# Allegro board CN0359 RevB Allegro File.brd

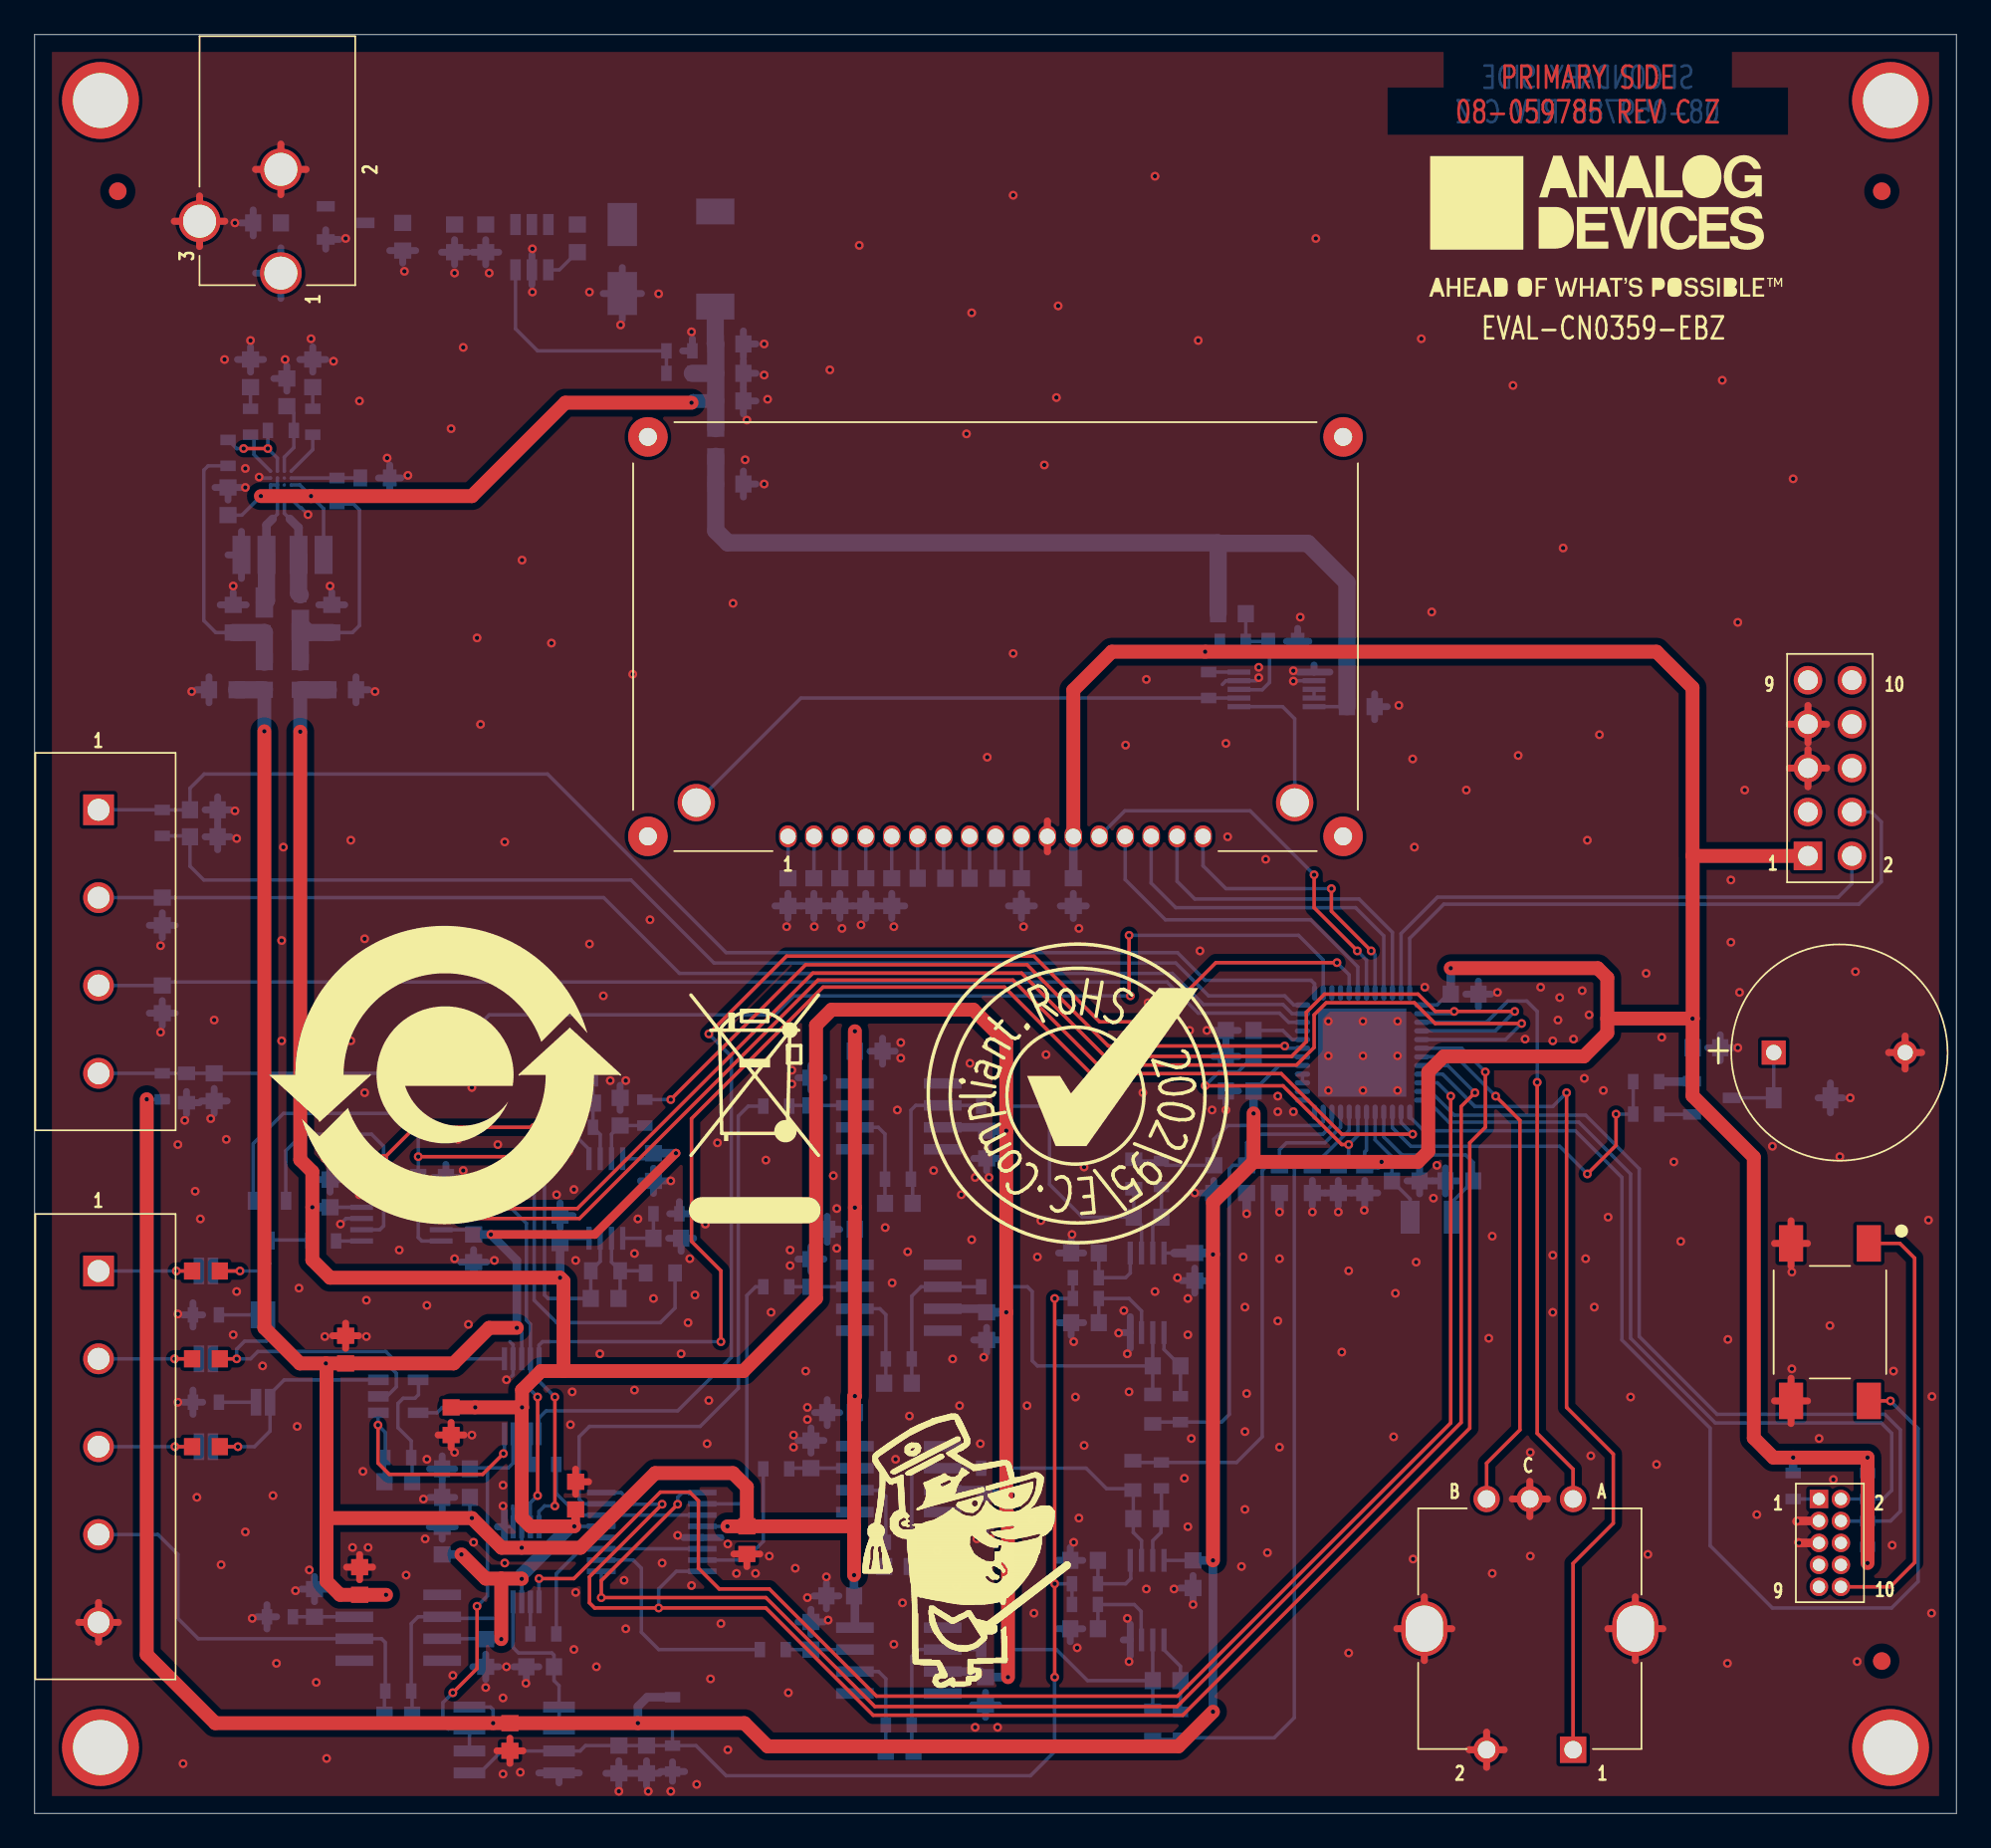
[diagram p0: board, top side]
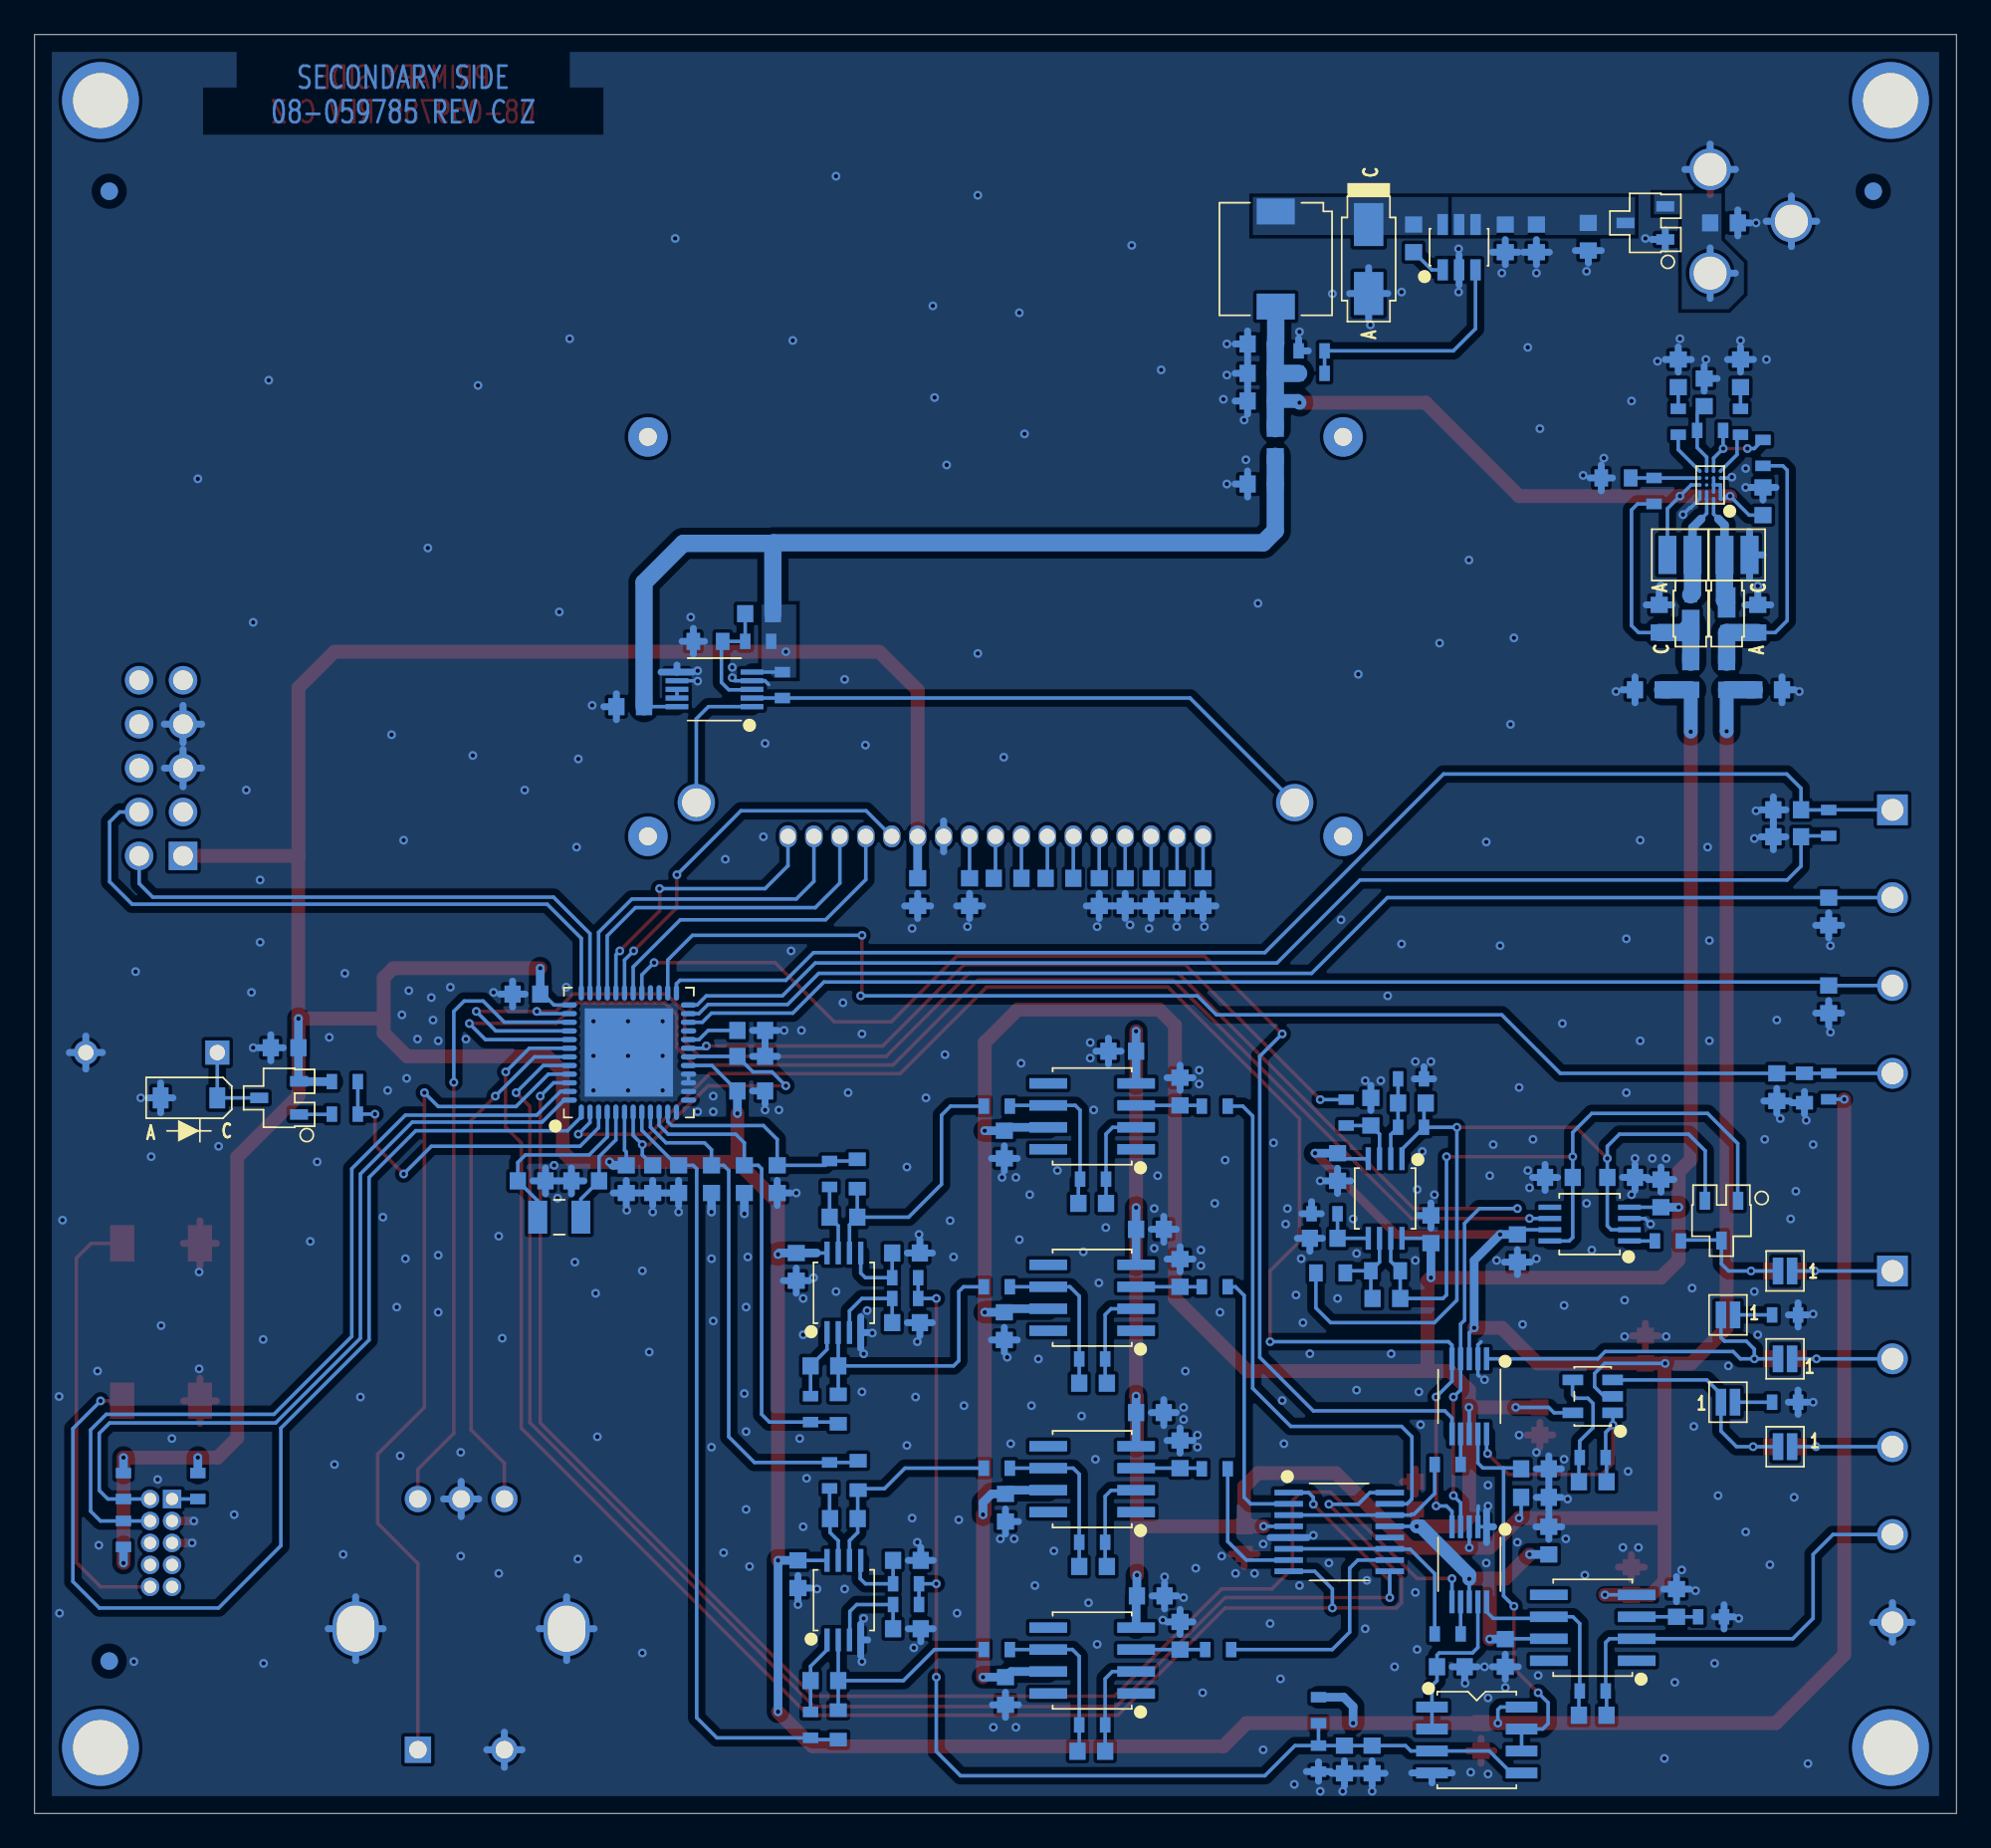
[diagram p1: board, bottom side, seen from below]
Outline 111.12 x 102.87 mm; copper layers: TOP, BOTTOM. Coordinates in mm from the lower left corner of the outline.
Outline path: 0,102.87 0,0 111.12,0 111.12,102.87 0,102.87

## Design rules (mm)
constraint set DEFAULT: min track width 0.203

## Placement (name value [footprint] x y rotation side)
C1  1UF  [C0603]  43.56 53.28 270 bottom
C2  1UF  [C0603]  17.98 26.82 90 top
C3  1UF  [C0603]  24.08 22.68 270 top
C4  1UF  [C0603]  31.29 18.38 90 top
C5  1UF  [C0603]  18.8 13.44 90 top
C6  1UF  [C0603]  41.19 15.8 270 top
C7  1UF  [C0603]  26.08 9.28 270 bottom
C8  1UF  [C0603]  27.48 4.42 270 top
C9  10uF  [C0603]  21.29 91.18 270 bottom
C12  10uF  [C0603]  11.19 75.88 90 bottom
C13  1UF  [C0603]  14.59 82.18 90 bottom
C15  0.1uF  [C0603]  13.44 91.98 180 bottom
C16  3300PF  [C0603]  12.49 83.28 90 bottom
C17  0.1uF  [C0603]  31.38 91.08 270 bottom
C18  10uF  [C0603]  24.29 91.08 270 bottom
C19  0.1uF  [C0603]  26.08 91.08 270 bottom
C21  10uF  [C0603]  17.18 69.09 90 bottom
C23  10uF  [C0603]  11.48 69.09 90 bottom
C24  1500PF  [C0603]  16.09 83.28 90 bottom
C25  0.1uF  [C0603]  40.19 84.98 0 bottom
C26  22UF  [C0603]  40.19 83.28 0 bottom
C27  0.1uF  [C0603]  76.69 64 0 bottom
C28  0.1uF  [C0603]  69.23 69.38 0 bottom
C29  0.01uF  [C0603]  17.79 64.98 0 bottom
C30  0.01uF  [C0603]  10.88 64.98 180 bottom
C31  10uF  [C0603]  40.19 81.68 0 bottom
C32  1UF  [C0603]  57.06 53.28 270 bottom
C33  1UF  [C0603]  54.86 54.08 0 bottom
C34  1UF  [C0603]  51.86 54.08 0 bottom
C35  0.1uF  [C0603]  60.06 53.28 270 bottom
C36  0.1uF  [C0603]  10.38 42 270 bottom
C37  0.1uF  [C0603]  7.38 52.16 270 bottom
C38  0.1uF  [C0603]  9.79 58.04 0 bottom
C39  0.1uF  [C0603]  9.79 56.48 0 bottom
C40  0.1uF  [C0603]  82.69 47.38 0 bottom
C41  0.1uF  [C0603]  7.38 47.08 270 bottom
C42  0.47UF  [C0603]  69.69 45.28 180 bottom
C43  0.1uF  [C0603]  96.67 44.28 0 bottom
C44  0.47UF  [C0603]  75.39 36.68 270 bottom
C45  1000pF  [C0603]  31.48 41.08 180 bottom
C46  1UF  [C0603]  35.79 37.38 270 bottom
C47  1UF  [C0603]  48.23 44.08 0 bottom
C48  1UF  [C0603]  69.69 41.78 180 bottom
C49  1UF  [C0603]  33.86 40.58 90 bottom
C50  4.7UF  [C0603]  44.89 41.75 90 bottom
C51  1UF  [C0603]  45.06 53.28 270 bottom
C52  0.01uF  [C0603]  68.19 36.68 270 bottom
C53  1UF  [C0603]  17.09 35.86 90 bottom
C54  1000pF  [C0603]  19.38 36.78 180 bottom
C55  820PF  [C0603]  64.36 34.48 0 bottom
C56  0.47UF  [C0603]  69.69 43.78 180 bottom
C57  0.1uF  [C0603]  76.91 36.68 270 bottom
C58  1UF  [C0603]  30.38 33.78 90 bottom
C59  1UF  [C0603]  36.59 33.26 0 bottom
C60  1000pF  [C0603]  49.97 35.28 0 bottom
C61  1UF  [C0603]  55.05 38.68 270 bottom
C62  1UF  [C0603]  60.74 32.41 180 bottom
C63  0.01uF  [C0603]  70.09 36.68 270 bottom
C64  0.01uF  [C0603]  73.89 36.68 270 bottom
C65  12pF  [C0603]  79.28 36.58 0 bottom
C66  12pF  [C0603]  82.39 36.58 180 bottom
C67  1000pF  [C0603]  22.98 36.78 0 bottom
C68  1000pF  [C0603]  32.96 29.78 180 bottom
C69  1UF  [C0603]  46.63 33.78 180 bottom
C70  1UF  [C0603]  25.38 32.68 270 bottom
C71  1UF  [C0603]  67.08 31.61 270 bottom
C72  0.01uF  [C0603]  71.98 36.68 270 bottom
C73  4.7UF  [C0603]  44.89 31.26 90 bottom
C74  1UF  [C0603]  60.74 28.38 180 bottom
C75  820PF  [C0603]  65.46 25.88 0 bottom
C76  1000pF  [C0603]  49.92 24.88 0 bottom
C77  1UF  [C0603]  55.05 28.18 270 bottom
C78  1000pF  [C0603]  21.03 19.18 180 bottom
C79  470pF  [C0603]  24.37 19.93 180 bottom
C80  1UF  [C0603]  46.63 23.18 180 bottom
C81  0.01uF  [C0603]  40.19 76.88 0 bottom
C82  1UF  [C0603]  24.37 18.28 180 bottom
C83  0.1uF  [C0603]  16.18 12.17 90 bottom
C84  4.7UF  [C0603]  44.89 20.77 90 bottom
C85  820PF  [C0603]  64.33 17.05 0 bottom
C86  1UF  [C0603]  23.57 15.78 90 bottom
C87  1000pF  [C0603]  49.92 14.28 0 bottom
C88  1UF  [C0603]  54.98 17.68 270 bottom
C89  1UF  [C0603]  60.69 14.63 180 bottom
C90  1UF  [C0603]  46.59 12.58 180 bottom
C91  1UF  [C0603]  66.98 13.83 270 bottom
C92  470pF  [C0603]  29.23 8.48 180 bottom
C93  4.7UF  [C0603]  44.89 10.28 90 bottom
C94  1UF  [C0603]  60.69 10.68 180 bottom
C95  1000pF  [C0603]  21.03 5.68 0 bottom
C96  820PF  [C0603]  65.46 7.68 0 bottom
C97  1000pF  [C0603]  50.02 3.6 0 bottom
C98  1UF  [C0603]  54.98 7.08 270 bottom
C99  1UF  [C0603]  33.79 3.12 270 bottom
C100  1UF  [C0603]  35.38 3.12 270 bottom
C101  1UF  [C0603]  46.56 53.28 270 bottom
C102  10uF  [C0603]  9.91 31.37 180 top
C103  1UF  [C0603]  9.91 26.29 0 top
C104  1UF  [C0603]  9.91 21.21 0 top
C105  1UF  [C0603]  48.06 53.28 270 bottom
C106  1UF  [C0603]  49.56 53.28 270 bottom
D1  PD3S140-7  [POWERDI323]  15.36 69.38 90 bottom
D2  PD3S140-7  [POWERDI323]  13.29 69.38 270 bottom
D3  B130-13-F  [SMA-2]  33.98 89.89 270 bottom
D4  MMSD4148T1G  [SOD123-2]  102.2 41.38 0 bottom
D5  BAT54SLT1G  [SOT23_B]  13.59 34.28 0 bottom
E1  100OHM  [L0603]  39.38 79.28 270 bottom
E2  100OHM  [L0603]  15.36 65.78 270 bottom
E3  100OHM  [L0603]  13.29 65.78 270 bottom
J1  PJ-102AH  [CNCUI-PJ-102A]  14.24 89.08 90 top
J2  SSW-105-01-G-D  [CNRCPT2X5H335LD35]  102.54 55.37 90 top
J3  OSTTC042162  [CNOSTTC042162]  3.7 58.04 270 top
J4  FTSH-105-01-L-D  [CNHDR2X5H219]  103.18 18.18 270 top
J5  OSTTC052162  [CNOSTTC052162]  3.7 31.37 270 top
JP1  -  [JPSLD02]  9.91 31.37 0 bottom
JP2  -  [JPSLD02]  9.91 26.29 0 bottom
JP3  -  [JPSLD02]  9.91 21.21 0 bottom
JP4  -  [JPSLD02]  13.21 28.83 0 bottom
JP5  -  [JPSLD02]  13.21 23.78 180 bottom
L1  4.7uH  [LSMSQ79H57]  15.99 72.78 0 bottom
L2  22UH  [LSMSQ236H189]  39.36 89.89 270 bottom
L3  8.2UH  [LSMSQ79H57]  12.69 72.78 0 bottom
NOREF  -  []  50.91 51.01 0 top
NOREF#2  -  []  86.46 3.98 0 top
NOREF#3  -  []  0 102.87 0 top
NOREF#4  -  [unnamed#2]  106.81 93.81 0 top
NOREF#5  -  []  140.51 149.31 0 top
NOREF#6  -  []  111.12 0 0 top
NOREF#7  -  []  0 0 0 top
NOREF#8  -  []  52.59 128.43 0 top
NOREF#9  -  []  0 102.87 270 top
NOREF#10  -  []  111.12 102.87 180 top
NOREF#11  -  []  126.31 186.91 0 top
NOREF#12  -  []  3.81 3.81 0 top
NOREF#13  -  [unnamed#2]  3.81 99.06 0 top
NOREF#14  -  []  23.71 42.71 0 top
NOREF#15  -  []  -22.69 -34.09 0 top
NOREF#16  -  []  111.12 0 90 top
NOREF#17  -  []  60.31 41.51 0 top
NOREF#18  -  []  3.81 3.81 0 top
NOREF#19  -  []  0 0 0 top
NOREF#20  -  [unnamed#2]  106.81 8.81 0 top
NOREF#21  -  []  -61.39 240.41 0 top
NOREF#22  -  []  0 102.87 0 top
NOREF#23  -  []  111.12 0 90 top
NOREF#24  -  []  0 0 0 top
NOREF#25  -  [unnamed#2]  107.31 99.06 0 top
NOREF#26  -  [unnamed#2]  107.31 3.81 0 top
NOREF#27  -  []  155.92 144.55 0 top
NOREF#28  -  []  -98.49 -107.79 0 top
NOREF#29  -  []  90.28 91.78 0 top
NOREF#30  -  [unnamed#2]  3.81 3.81 0 top
NOREF#31  -  [unnamed#2]  4.81 93.81 0 top
NOREF#32  -  []  85.48 94.48 270 top
NOREF#33  -  []  -106.09 -141.79 0 top
NOREF#34  -  []  121.61 28.31 0 top
NOREF#35  -  []  155.97 121.69 0 top
NOREF#36  -  [unnamed#2]  106.81 93.81 180 bottom
NOREF#37  -  [unnamed#2]  4.81 93.81 180 bottom
NOREF#38  -  [unnamed#2]  106.81 8.81 180 bottom
Q1  SMMBT3906LT3G  [SOT23_B]  96.98 41.38 90 bottom
R1  14.3K  [R0603]  16.09 80.48 90 bottom
R2  2.43K  [R0603]  37.29 84.58 0 bottom
R3  2.43MEG  [R0603]  17.48 76.48 90 bottom
R4  137K  [R0603]  19.68 77.23 0 bottom
R5  7.5K  [R0603]  37.29 83.28 180 bottom
R6  13.7  [R0603]  67.89 65.25 270 bottom
R7  35.7K  [R0603]  72.19 67.78 0 bottom
R8  5.11K  [R0603]  69.28 67.78 0 bottom
R9  0  [R0603]  101.69 18.93 270 bottom
R10  100K  [R0603]  105.98 16.16 90 bottom
R11  1K  [R0603]  7.38 42.05 90 bottom
R12  35.7  [R0603]  8.79 41.95 270 bottom
R13  1.5K  [R0603]  7.38 57.28 90 bottom
R14  110K  [R0603]  31.54 39.68 180 bottom
R15  15K  [R0603]  31.54 42.48 0 bottom
R16  13.3K  [R0603]  35.29 40.53 270 bottom
R17  47.5K  [R0603]  93.19 42.32 180 bottom
R18  2.74K  [R0603]  93.19 40.44 0 bottom
R19  7.5K  [R0603]  55.48 40.9 0 bottom
R20  1.2K  [R0603]  63.56 36.98 90 bottom
R21  24.3  [R0603]  65.16 36.98 90 bottom
R22  13.3K  [R0603]  36.53 34.68 180 bottom
R23  1K  [R0603]  16.68 33.1 0 bottom
R24  26.7K  [R0603]  36.19 31.26 180 bottom
R25  1K  [R0603]  49.92 36.68 0 bottom
R26  1K  [R0603]  60.79 30.98 0 bottom
R27  26.7K  [R0603]  33.01 31.38 180 bottom
R28  1K  [R0603]  60.79 29.78 0 bottom
R29  7.5K  [R0603]  55.48 30.46 0 bottom
R30  1K  [R0603]  49.97 26.28 0 bottom
R31  1.2K  [R0603]  64.66 23.38 270 bottom
R32  24.3  [R0603]  66.26 23.38 270 bottom
R33  432  [R0603]  29.42 20.18 0 bottom
R34  432  [R0603]  42.89 40.9 0 bottom
R35  475K  [R0603]  21.03 20.58 180 bottom
R36  432  [R0603]  42.89 30.46 0 bottom
R37  7.5K  [R0603]  55.48 19.97 0 bottom
R38  1.2K  [R0603]  63.51 19.55 90 bottom
R39  24.3  [R0603]  65.16 19.55 90 bottom
R40  1K  [R0603]  14.19 11.37 0 bottom
R41  432  [R0603]  42.89 19.93 0 bottom
R42  432  [R0603]  42.69 9.48 0 bottom
R43  1K  [R0603]  49.97 15.68 0 bottom
R44  1K  [R0603]  60.74 13.28 0 bottom
R45  432  [R0603]  29.42 10.38 0 bottom
R46  1K  [R0603]  60.74 12.08 0 bottom
R47  1K  [R0603]  21.03 7.08 0 bottom
R48  7.5K  [R0603]  55.48 9.48 0 bottom
R49  10K  [R0603]  36.89 5.97 270 bottom
R50  10K  [R0603]  36.89 3.17 270 bottom
R51  1K  [R0603]  49.97 5.12 0 bottom
R52  1.2K  [R0603]  64.66 5.12 270 bottom
R53  24.3  [R0603]  66.26 5.12 270 bottom
R54  100K  [R0603]  105.98 18.93 270 bottom
R55  1MEG  [R0603]  9.91 28.83 180 bottom
R56  1MEG  [R0603]  9.91 23.78 0 bottom
R57  2.32MEG  [R0603]  11.19 78.68 90 bottom
R58  118K  [R0603]  14.24 79.98 0 bottom
R59  10.5K  [R0603]  12.49 80.48 90 bottom
S1  PEC12R-4130F-S0012  [BOURNS_PEC12R-4XXXF-SXXXX]  88.96 3.68 180 top
S2  FSM2JSMA  [SWSMSQ236H185]  103.81 28.41 180 top
U1  NHD-C12832A1Z-NSW-BBW-3V3  [MNHD-C12832A1Z]  43.56 56.5 0 top
U2  WST-1203UX  [TORAD299D472H315]  100.56 44 0 top
U3  SI2343CDS-T1-GE3  [SOT23_B]  17.98 91.98 90 bottom
U4  ADP2300AUJZ  [TSOT23_6]  28.76 90.58 180 bottom
U5  ADP5072ACBZ  [WLCSP20H22]  14.24 76.82 90 bottom
U6  AD8592ARMZ  [RM10]  71.81 65 90 bottom
U7  ADUCM360BCPZ128  [QFN48_7X7_PAD5_1X5_1]  76.76 44 180 bottom
U9  ADA4077-2ARMZ  [MSOP8]  33.03 35.56 0 bottom
U10  ADA4638-1ARZ  [SO8]  49.97 40.31 90 bottom
U11  ADG1419BRMZ  [MSOP8]  21.21 34.08 90 bottom
U12  ADA4528-2ARMZ  [MSOP8]  64.33 30.11 180 bottom
U13  ADA4638-1ARZ  [SO8]  49.97 29.82 90 bottom
U14  ADA4622-1ARJZ  [SOT23-5L-2]  21.03 24.12 90 bottom
U15  AD8253ARMZ  [RM10]  28.17 24.12 0 bottom
U16  ADA4638-1ARZ  [SO8]  49.97 19.33 90 bottom
U17  ADG1211YRUZ  [TSSOP16]  35.69 16.28 270 bottom
U18  AD8253ARMZ  [RM10]  28.17 14.41 0 bottom
U19  ADA4627-1ARZ  [SO8]  21.03 10.74 90 bottom
U20  ADA4528-2ARMZ  [MSOP8]  64.33 12.33 180 bottom
U21  ADA4638-1ARZ  [SO8]  49.97 8.84 90 bottom
U22  AD8542ARZ  [SO8NB-5]  27.73 4.25 270 bottom
Y1  0.032768MEGHZ  [YSML126W59H35]  80.78 34.48 180 bottom

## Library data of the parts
C1-C8 C13 C32-C34 C46-C49 C51 C53 C58 C59 C61 C62 C69-C71 C74 C77 C80 C82 C86 C88-C91 C94 C98-C101 C103-C106 = CAP: User Part Number: UPN; Tolerance: 10; alternate symbols: (C0603L); part number: CAP_SM-1UF,25V,10,E048498,C0603; tolerance: 10
C9 C12 C18 C21 C23 C31 C102 = CAP: User Part Number: UPN; Tolerance: 10; alternate symbols: (C0603L); part number: CAP_SM-10UF,25V,10,E030977,C0603; tolerance: 10
C15 C17 C19 C25 C27 C28 C35-C41 C43 C57 C83 = CAP: User Part Number: UPN; Tolerance: 10; alternate symbols: (C0603L); part number: CAP_SM-0.1UF,25V,10,E038719,C0603; tolerance: 10
C16 = CAP: User Part Number: UPN; Tolerance: 10; alternate symbols: (C0603L); part number: CAP_SM-3300PF,25V,10,E058968,C0603; tolerance: 10
C24 = CAP: User Part Number: UPN; Tolerance: 10; alternate symbols: (C0603L); part number: CAP_SM-1500PF,16V,10,E058957,C0603; tolerance: 10
C26 = CAP: User Part Number: UPN; Tolerance: 20; alternate symbols: (C0603L); part number: CAP_SM-22UF,16V,20,E049658,C0603; tolerance: 20
C29 C30 C52 C63 C64 C72 C81 = CAP: User Part Number: UPN; Tolerance: 10; alternate symbols: (C0603L); part number: CAP_SM-0.01UF,50V,10,E018587,C0603; tolerance: 10
C42 C44 C56 = CAP: User Part Number: UPN; Tolerance: 10; alternate symbols: (C0603L); part number: CAP_SM-0.47UF,25V,10,E048456,C0603; tolerance: 10
C45 C54 C60 C67 C68 C76 C78 C87 C95 C97 = CAP: User Part Number: UPN; Tolerance: 10; alternate symbols: (C0603L); part number: CAP_SM-1000PF,50V,10,E018586,C0603; tolerance: 10
C50 C73 C84 C93 = CAP: User Part Number: UPN; Tolerance: 10; alternate symbols: (C0603L); part number: CAP_SM-4.7UF,25V,10,E058970,C0603; tolerance: 10
C55 C75 C85 C96 = CAP: User Part Number: UPN; Tolerance: 10; alternate symbols: (C0603L); part number: CAP_SM-820PF,50V,10,E058971,C0603; tolerance: 10
C65 C66 = CAP: User Part Number: UPN; Tolerance: 5; alternate symbols: (C0603L); part number: CAP_SM-12PF,50V,5,E000343,C0603; tolerance: 5
C79 C92 = CAP: User Part Number: UPN; Tolerance: 10; alternate symbols: (C0603L); part number: CAP_SM-470PF,50V,10,E025632,C0603; tolerance: 10
D1 D2 = DIOSCHOTTKY: Tolerance: N/A; User Part Number: UPN; alternate symbols: (); part number: DIOSCHOTTKY_SM-PD3S140-7,60V,N/A,E017965,POWERDI323; tolerance: N/A
D3 = DIOSCHOTTKY: User Part Number: UPN; Tolerance: N/A; alternate symbols: (); part number: DIOSCHOTTKY_SM-B130-13-F,30V,N/A,E029499,SMA-2; tolerance: N/A
D4 = DIO: User Part Number: UPN; Tolerance: N/A; alternate symbols: (); part number: DIO_SM-MMSD4148T1G,100V,N/A,E005349,SOD123-2; tolerance: N/A
D5 = DIOSCHOTTKY3P_V14: User Part Number: UPN; Tolerance: N/A; alternate symbols: (); part number: DIOSCHOTTKY3P_V14_SM-BAT54SLT1G,30V,N/A,E035143,SOT23_B; tolerance: N/A
E1-E3 = FERRITE: User Part Number: UPN; Tolerance: N/A; alternate symbols: (L0603L); part number: FERRITE_SM-100OHM,N/A,E011938,L0603; tolerance: N/A
J1 = CN3P: Tolerance: N/A; User Part Number: UPN; alternate symbols: (); part number: CN3P_TH-PJ-102AH,E010074,CNCUI-PJ-102A; tolerance: N/A
J2 = CN10P: Tolerance: N/A; User Part Number: UPN; alternate symbols: (); part number: CN10P_TH-SSW-105-01-G-D,E012830,CNRCPT2X5H335LD35; tolerance: N/A
J3 = CN4P: User Part Number: UPN; Tolerance: N/A; alternate symbols: (); part number: CN4P_TH-OSTTC042162,E027760,CNOSTTC042162; tolerance: N/A
J4 = CN10P_ODD_EVEN: Tolerance: N/A; User Part Number: UPN; alternate symbols: (); part number: CN10P_ODD_EVEN_TH-FTSH-105-01-L-D,E018623,CNHDR2X5H219; tolerance: N/A
J5 = CN5P: User Part Number: UPN; Tolerance: N/A; alternate symbols: (); part number: CN5P_TH-OSTTC052162,E025296,CNOSTTC052162; tolerance: N/A
JP1-JP5 = NC2P: User Part Number: UPN; Tolerance: N/A; alternate symbols: (); part number: NC2P_SM-JPSLD02,E006230,JPSLD02; tolerance: N/A
L1 = IND: Tolerance: 20; User Part Number: UPN; alternate symbols: (); part number: IND_SM-4.7UH,20,E016399,LSMSQ79H57; tolerance: 20
L2 = IND: Tolerance: 20; User Part Number: UPN; alternate symbols: (); part number: IND_SM-22UH,20,E040512,LSMSQ236H189; tolerance: 20
L3 = IND: Tolerance: 20; User Part Number: UPN; alternate symbols: (); part number: IND_SM-8.2UH,20,E047498,LSMSQ79H57; tolerance: 20
Q1 = TRANPNP_V3: User Part Number: UPN; Tolerance: N/A; alternate symbols: (); part number: TRANPNP_V3_SM-SMMBT3906LT3G,E056389,SOT23_B; tolerance: N/A
R1 = RES: User Part Number: UPN; Tolerance: 1; alternate symbols: (R0603L); part number: RES_SM-14.3K,E058987,1/10W,1,R0603; tolerance: 1
R2 = RES: User Part Number: UPN; Tolerance: 1; alternate symbols: (R0603L); part number: RES_SM-2.43K,E042601,1/10W,1,R0603; tolerance: 1
R3 = RES: User Part Number: UPN; Tolerance: 1; alternate symbols: (R0603L); part number: RES_SM-2.43MEG,E026607,1/10W,1,R0603; tolerance: 1
R4 = RES: User Part Number: UPN; Tolerance: 1; alternate symbols: (R0603L); part number: RES_SM-137K,E044643,1/10W,1,R0603; tolerance: 1
R5 = RES: User Part Number: UPN; Tolerance: 1; alternate symbols: (R0603L); part number: RES_SM-7.5K,E006439,1/10W,1,R0603; tolerance: 1
R6 = RES: User Part Number: UPN; Tolerance: 1; alternate symbols: (R0603L); part number: RES_SM-13.7,E058986,1/10W,1,R0603; tolerance: 1
R7 = RES: User Part Number: UPN; Tolerance: 1; alternate symbols: (R0603L); part number: RES_SM-35.7K,E016592,1/10W,1,R0603; tolerance: 1
R8 = RES: User Part Number: UPN; Tolerance: 1; alternate symbols: (R0603L); part number: RES_SM-5.11K,E026136,1/10W,1,R0603; tolerance: 1
R9 = RES: User Part Number: UPN; Tolerance: JUMPER; alternate symbols: (R0603L); part number: RES_SM-0,E054377,1/10W,JUMPER,R0603; tolerance: JUMPER
R10 R54 = RES: User Part Number: UPN; Tolerance: 1; alternate symbols: (R0603L); part number: RES_SM-100K,E017050,1/10W,1,R0603; tolerance: 1
R11 R23 R25 R26 R28 R30 R40 R43 R44 R46 R51 = RES: User Part Number: UPN; Tolerance: 1; alternate symbols: (R0603L); part number: RES_SM-1K,E029591,1/10W,1,R0603; tolerance: 1
R12 = RES: User Part Number: UPN; Tolerance: 1; alternate symbols: (R0603L); part number: RES_SM-35.7,E006398,1/10W,1,R0603; tolerance: 1
R13 = RES: User Part Number: UPN; Tolerance: 0.1; alternate symbols: (R0603L); part number: RES_SM-1.5K,E010316,1/10W,0.1,R0603; tolerance: 0.1
R14 = RES: User Part Number: UPN; Tolerance: 0.1; alternate symbols: (R0603L); part number: RES_SM-110K,E058984,1/10W,0.1,R0603; tolerance: 0.1
R15 = RES: User Part Number: UPN; Tolerance: 0.1; alternate symbols: (R0603L); part number: RES_SM-15K,E019547,1/10W,0.1,R0603; tolerance: 0.1
R16 R22 = RES: User Part Number: UPN; Tolerance: 1; alternate symbols: (R0603L); part number: RES_SM-13.3K,E049888,1/10W,1,R0603; tolerance: 1
R17 = RES: User Part Number: UPN; Tolerance: 1; alternate symbols: (R0603L); part number: RES_SM-47.5K,E032237,1/10W,1,R0603; tolerance: 1
R18 = RES: User Part Number: UPN; Tolerance: 1; alternate symbols: (R0603L); part number: RES_SM-2.74K,E003698,1/10W,1,R0603; tolerance: 1
R19 R29 R37 R48 = RES: User Part Number: UPN; Tolerance: 0.1; alternate symbols: (R0603L); part number: RES_SM-7.5K,E059024,1/5W,0.1,R0603; tolerance: 0.1
R20 R31 R38 R52 = RES: User Part Number: UPN; Tolerance: 0.1; alternate symbols: (R0603L); part number: RES_SM-1.2K,E039264,1/10W,0.1,R0603; tolerance: 0.1
R21 R32 R39 R53 = RES: User Part Number: UPN; Tolerance: 1; alternate symbols: (R0603L); part number: RES_SM-24.3,E059028,1/10W,1,R0603; tolerance: 1
R24 R27 = RES: User Part Number: UPN; Tolerance: 0.1; alternate symbols: (); part number: RES_SM-26.7K,E059128,1/5W,0.1,R0603; tolerance: 0.1
R33 R34 R36 R41 R42 R45 = RES: User Part Number: UPN; Tolerance: 1; alternate symbols: (R0603L); part number: RES_SM-432,E059030,1/10W,1,R0603; tolerance: 1
R35 = RES: User Part Number: UPN; Tolerance: 1; alternate symbols: (R0603L); part number: RES_SM-475K,E032846,1/10W,1,R0603; tolerance: 1
R47 = RES: User Part Number: UPN; Tolerance: 0.1; alternate symbols: (R0603L); part number: RES_SM-1K,E010662,1/10W,0.1,R0603; tolerance: 0.1
R49 R50 = RES: User Part Number: UPN; Tolerance: 1; alternate symbols: (R0603L); part number: RES_SM-10K,E058983,1/10W,1,R0603; tolerance: 1
R55 R56 = RES: User Part Number: UPN; Tolerance: 1; alternate symbols: (R0603L); part number: RES_SM-1MEG,E003682,1/10W,1,R0603; tolerance: 1
R57 = RES: User Part Number: UPN; Tolerance: 1; alternate symbols: (R0603L); part number: RES_SM-2.32MEG,E029679,1/10W,1,R0603; tolerance: 1
R58 = RES: User Part Number: UPN; Tolerance: 1; alternate symbols: (R0603L); part number: RES_SM-118K,E058985,1/10W,1,R0603; tolerance: 1
R59 = RES: User Part Number: UPN; Tolerance: 1; alternate symbols: (R0603L); part number: RES_SM-10.5K,E058980,1/10W,1,R0603; tolerance: 1
S1 = SWENCODER5P_2PSHLD: User Part Number: UPN; Tolerance: N/A; alternate symbols: (); part number: SWENCODER5P_2PSHLD_TH-PEC12R-4130F-S0012,E027763,BOURNS_PEC12R-4XXXF-SXXXX; tolerance: N/A
S2 = SWSPST4PIN_B: User Part Number: UPN; Tolerance: N/A; alternate symbols: (); part number: SWSPST4PIN_B_SM-FSM2JSMA,E016530,SWSMSQ236H185; tolerance: N/A
U1 = MOD_NHD_C12832A1Z: User Part Number: UPN; Tolerance: N/A; alternate symbols: (); part number: MOD_NHD_C12832A1Z_TH-NHD-C12832A1Z-NSW-BBW-3V3,E019272,MNHD-C12832A1Z; tolerance: N/A
U2 = ICWST_1203UX: User Part Number: UPN; Tolerance: N/A; alternate symbols: (); part number: ICWST_1203UX_TH-WST-1203UX,E050821,TORAD299D472H315; tolerance: N/A
U3 = TRANPMOSFET_V12: User Part Number: UPN; Tolerance: N/A; alternate symbols: (); part number: TRANPMOSFET_V12_SM-SI2343CDS-T1-GE3,E042394,SOT23_B; tolerance: N/A
U4 = ADP2301: User Part Number: UPN; Tolerance: N/A; alternate symbols: (); part number: ADP2301_SM-ADP2300AUJZ,E013639,TSOT23_6; tolerance: N/A
U5 = ADP5072: Tolerance: N/A; User Part Number: UPN; alternate symbols: (); part number: ADP5072_SM-ADP5072ACBZ,E030798,WLCSP20H22; tolerance: N/A
U6 = AD8592: Tolerance: N/A; User Part Number: UPN; alternate symbols: (); part number: AD8592_SM-AD8592ARMZ,E025174,RM10; tolerance: N/A
U7 = ADUCM36X: User Part Number: UPN; Tolerance: N/A; alternate symbols: (); part number: ADUCM36X_SM-ADUCM360BCPZ128,E018148,QFN48_7X7_PAD5_1X5_1; tolerance: N/A
U9 = ADA4077_2: Tolerance: N/A; User Part Number: UPN; alternate symbols: (); part number: ADA4077_2_SM-ADA4077-2ARMZ,E026580,MSOP8; tolerance: N/A
U10 U13 U16 U21 = ADOPAMP1V4: Tolerance: N/A; User Part Number: UPN; alternate symbols: (); part number: ADOPAMP1V4_SM-ADA4638-1ARZ,E015446,SO8; tolerance: N/A
U11 = ADG1419: Tolerance: N/A; User Part Number: UPN; alternate symbols: (); part number: ADG1419_SM-ADG1419BRMZ,E014853,MSOP8; tolerance: N/A
U12 U20 = ADA4528_2: Tolerance: N/A; User Part Number: UPN; alternate symbols: (); part number: ADA4528_2_SM-ADA4528-2ARMZ,E018592,MSOP8; tolerance: N/A
U14 = ADA4622_1_V2: User Part Number: UPN; Tolerance: N/A; alternate symbols: (); part number: ADA4622_1_V2_SM-ADA4622-1ARJZ,E038112,SOT23-5L-2; tolerance: N/A
U15 U18 = AD8253: Tolerance: N/A; User Part Number: UPN; alternate symbols: (); part number: AD8253_SM-AD8253ARMZ,E008097,RM10; tolerance: N/A
U17 = ADG1611: Tolerance: N/A; User Part Number: UPN; alternate symbols: (); part number: ADG1611_SM-ADG1211YRUZ,E012179,TSSOP16; tolerance: N/A
U19 = ADA46X7: Tolerance: N/A; User Part Number: UPN; alternate symbols: (); part number: ADA46X7_SM-ADA4627-1ARZ,E012263,SO8; tolerance: N/A
U22 = ADOPAMP2: Tolerance: N/A; User Part Number: UPN; alternate symbols: (); part number: ADOPAMP2_SM-AD8542ARZ,E004993,SO8NB-5; tolerance: N/A
Y1 = XTAL: User Part Number: UPN; Tolerance: 20PPM; alternate symbols: (); part number: XTAL_SM-0.032768MEGHZ,E019185,YSML126W59H35; tolerance: 20PPM

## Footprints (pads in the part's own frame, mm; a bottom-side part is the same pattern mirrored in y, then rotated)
BOURNS_PEC12R-4XXXF-SXXXX
  rect 1.524x1.524 hole 1.016: 1(0,0)
  round 1.524 hole 1.016: 2(5,0) A(0,-14.5) B(5,-14.5) C(2.5,-14.5)
  oval 2.667x3.175 hole 2.159x2.667: SH1(-3.6,-7) SH2(8.6,-7)
C0603
  rect 0.94x0.991 smd: 1(-0.8,0) 2(0.8,0)
CNCUI-PJ-102A
  round 2.413 hole 1.905: 1(0,0) 2(6,0) 3(3,4.7)
CNHDR2X5H219
  rect 1.067x1.067 hole 0.711: 1(0,0)
  round 1.067 hole 0.711: 2(0,1.27) 3(1.27,0) 4(1.27,1.27) 5(2.54,0) 6(2.54,1.27) 7(3.81,0) 8(3.81,1.27) 9(5.08,0) 10(5.08,1.27)
CNOSTTC042162
  rect 1.778x1.778 hole 1.27: 1(0,0)
  round 1.778 hole 1.27: 2(5.08,0) 3(10.16,0) 4(15.24,0)
CNOSTTC052162
  rect 1.778x1.778 hole 1.27: 1(0,0)
  round 1.778 hole 1.27: 2(5.08,0) 3(10.16,0) 4(15.24,0) 5(20.32,0)
CNRCPT2X5H335LD35
  rect 1.651x1.651 hole 1.143: 1(0,0)
  round 1.651 hole 1.143: 2(0,-2.54) 3(2.54,0) 4(2.54,-2.54) 5(5.08,0) 6(5.08,-2.54) 7(7.62,0) 8(7.62,-2.54) 9(10.16,0) 10(10.16,-2.54)
JPSLD02
  rect 0.61x1.549 smd: 1(-0.406,0) 2(0.406,0)
L0603
  rect 0.94x0.991 smd: 1(-0.8,0) 2(0.8,0)
LSMSQ79H57
  rect 1.041x2.21 smd: 1(-0.724,0) 2(0.724,0)
LSMSQ236H189
  rect 1.499x2.21 smd: 1(-2.749,0) 2(2.749,0)
MNHD-C12832A1Z
  round 2.286 hole 1.041 unplated: (-8.1,23.1) (-8.1,0) (32.1,23.1) (32.1,0)
  oval 1.016x1.27 hole 0.889: 1(0,0) 2(1.5,0) 3(3,0) 4(4.5,0) 5(6,0) 6(7.5,0) 7(9,0) 8(10.5,0) 9(12,0) 10(13.5,0) 11(15,0) 12(16.5,0) 13(18,0) 14(19.5,0) 15(21,0) 16(22.5,0) 17(24,0)
  round 2.159 hole 1.651: A(-5.3,1.95) K(29.3,1.95)
MSOP8
  rect 0.305x1.321 smd: 1(-0.975,-2.3) 2(-0.325,-2.3) 3(0.325,-2.3) 4(0.975,-2.3) 5(0.975,2.3) 6(0.325,2.3) 7(-0.325,2.3) 8(-0.975,2.3)
POWERDI323
  rect 0.864x0.737 smd: A(1.09,0)
  rect 1.753x1.016 smd: C(-0.65,0)
QFN48_7X7_PAD5_1X5_1
  oval 0.305x0.889 smd: 1(-2.75,-3.45) 2(-2.25,-3.45) 3(-1.75,-3.45) 4(-1.25,-3.45) 5(-0.75,-3.45) 6(-0.25,-3.45) 7(0.25,-3.45) 8(0.75,-3.45) 9(1.25,-3.45) 10(1.75,-3.45) 11(2.25,-3.45) 12(2.75,-3.45) 25(2.75,3.45) 26(2.25,3.45) 27(1.75,3.45) 28(1.25,3.45) 29(0.75,3.45) 30(0.25,3.45) 31(-0.25,3.45) 32(-0.75,3.45) 33(-1.25,3.45) 34(-1.75,3.45) 35(-2.25,3.45) 36(-2.75,3.45)
  oval 0.889x0.305 smd: 13(3.45,-2.75) 14(3.45,-2.25) 15(3.45,-1.75) 16(3.45,-1.25) 17(3.45,-0.75) 18(3.45,-0.25) 19(3.45,0.25) 20(3.45,0.75) 21(3.45,1.25) 22(3.45,1.75) 23(3.45,2.25) 24(3.45,2.75) 37(-3.45,2.75) 38(-3.45,2.25) 39(-3.45,1.75) 40(-3.45,1.25) 41(-3.45,0.75) 42(-3.45,0.25) 43(-3.45,-0.25) 44(-3.45,-0.75) 45(-3.45,-1.25) 46(-3.45,-1.75) 47(-3.45,-2.25) 48(-3.45,-2.75)
  rect 5.105x5.105 smd: PAD(0,0)
R0603
  rect 0.61x0.889 smd: 1(-0.75,0) 2(0.75,0)
RM10
  rect 0.305x1.321 smd: 1(-1,-2.171) 2(-0.5,-2.171) 3(0,-2.171) 4(0.5,-2.171) 5(1,-2.171) 6(1,2.171) 7(0.5,2.171) 8(0,2.171) 9(-0.5,2.171) 10(-1,2.171)
SMA-2
  rect 2.489x1.702 smd: A(1.995,0) C(-1.995,0)
SO8
  rect 0.61x2.184 smd: 1(-1.905,-2.54) 2(-0.635,-2.54) 3(0.635,-2.54) 4(1.905,-2.54) 5(1.905,2.54) 6(0.635,2.54) 7(-0.635,2.54) 8(-1.905,2.54)
SO8NB-5
  rect 0.635x1.829 smd: 1(-1.905,-2.591) 2(-0.635,-2.591) 3(0.635,-2.591) 4(1.905,-2.591) 5(1.905,2.591) 6(0.635,2.591) 7(-0.635,2.591) 8(-1.905,2.591)
SOD123-2
  rect 0.914x1.219 smd: A(1.638,0) C(-1.638,0)
SOT23-5L-2
  rect 0.61x1.194 smd: 1(-0.95,-1.15) 2(0,-1.15) 3(0.95,-1.15) 4(0.95,1.15) 5(-0.95,1.15)
SOT23_B
  rect 0.61x1.041 smd: 1(-0.958,-1.15) 2(0.958,-1.15) 3(0,1.15)
SWSMSQ236H185
  rect 1.397x2.108 smd: 1(-2.248,-4.554) 2(-2.248,4.554) 3(2.248,-4.554) 4(2.248,4.554)
TORAD299D472H315
  round 1.397 hole 0.889: N(7.6,0)
  rect 1.397x1.397 hole 0.889: P(0,0)
TSOT23_6
  rect 0.61x1.219 smd: 1(-0.95,-1.31) 2(0,-1.31) 3(0.95,-1.31) 4(0.95,1.31) 5(0,1.31) 6(-0.95,1.31)
TSSOP16
  rect 0.33x1.651 smd: 1(-2.275,-2.92) 2(-1.625,-2.92) 3(-0.975,-2.92) 4(-0.325,-2.92) 5(0.325,-2.92) 6(0.975,-2.92) 7(1.625,-2.92) 8(2.275,-2.92) 9(2.275,2.92) 10(1.625,2.92) 11(0.975,2.92) 12(0.325,2.92) 13(-0.325,2.92) 14(-0.975,2.92) 15(-1.625,2.92) 16(-2.275,2.92)
unnamed#2
  round 1.016 smd: (0,0)
WLCSP20H22
  round 0.203 smd: A1(-0.8,-0.6) A2(-0.8,-0.2) A3(-0.8,0.2) A4(-0.8,0.6) B1(-0.4,-0.6) B2(-0.4,-0.2) B3(-0.4,0.2) B4(-0.4,0.6) C1(0,-0.6) C2(0,-0.2) C3(0,0.2) C4(0,0.6) D1(0.4,-0.6) D2(0.4,-0.2) D3(0.4,0.2) D4(0.4,0.6) E1(0.8,-0.6) E2(0.8,-0.2) E3(0.8,0.2) E4(0.8,0.6)
YSML126W59H35
  rect 1.092x1.905 smd: 1(-1.246,0) 2(1.246,0)

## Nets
+3.3V: C8.1 C27.1 C28.1 C35.1 C40.1 C43.1 C48.1 C57.1 C71.1 C81.1 C91.1 E1.2(N2) J2.1 Q1.2(E) R6.1 R8.1 R9.1 R10.1 R11.1 R17.1 R49.1 R54.1 U1.12 U6.5 U6.10 U7.6 U7.17 U7.37 U12.8 U20.8 U22.8
+15V: C3.1 C4.1 C7.1 C29.1 C53.1 C58.1 C61.1 C77.1 C86.1 C88.1 C98.1 E2.2(N2) U9.8 U10.7 U11.4 U13.7 U14.5 U15.8 U16.7 U17.13 U18.8 U19.7 U21.7
-15V: C2.1 C5.1 C6.1 C30.1 C46.1 C47.1 C69.1 C70.1 C80.1 C82.1 C90.1 E3.2(N2) U9.4(V-) U10.4(V-) U11.7(VSS) U13.4(V-) U14.2(V-) U15.3 U16.4(V-) U17.4(VSS) U18.3 U19.4(V-) U21.4(V-)
GND: C1.2(N2) C2.2(N2) C3.2(N2) C4.2(N2) C5.2(N2) C6.2(N2) C7.2(N2) C8.2(N2) C9.2(N2) C12.2(N2) C13.2(N2) C15.2(N2) C16.2(N2) C18.2(N2) C19.2(N2) C21.2(N2) C23.2(N2) C24.2(N2) C25.2(N2) C26.2(N2) C27.2(N2) C29.2(N2) C30.2(N2) C31.2(N2) C32.2(N2) C35.2(N2) C36.2(N2) C37.2(N2) C38.2(N2) C39.2(N2) C40.2(N2) C41.2(N2) C42.2(N2) C43.2(N2) C44.2(N2) C46.2(N2) C47.2(N2) C48.2(N2) C49.2(N2) C50.2(N2) C51.2(N2) C52.2(N2) C53.2(N2) C54.2(N2) C56.2(N2) C57.2(N2) C58.2(N2) C59.2(N2) C61.2(N2) C62.2(N2) C63.2(N2) C64.2(N2) C65.2(N2) C66.2(N2) C67.2(N2) C69.2(N2) C70.2(N2) C71.2(N2) C72.2(N2) C73.2(N2) C74.2(N2) C77.2(N2) C79.2(N2) C80.2(N2) C81.2(N2) C82.2(N2) C83.2(N2) C84.2(N2) C86.2(N2) C88.2(N2) C89.2(N2) C90.2(N2) C91.2(N2) C92.2(N2) C93.2(N2) C94.2(N2) C98.2(N2) C99.2(N2) C100.2(N2) C101.2(N2) C105.2(N2) C106.2(N2) D3.A(P) D4.A(P) J1.2 J1.3(N3) J2.5 J2.7 J4.3 J4.5 J5.5(N5) L3.1 R2.2(N2) R4.2(N2) R7.2(N2) R12.2(N2) R15.1 R22.1 R40.1 R50.2(N2) R55.2(N2) R56.1 S1.2 S1.C S1.SH1 S1.SH2 S2.3 S2.4(N4) U1.11(VSS) U2.N(N2) U3.1 U4.2 U5.A4 U5.B4 U5.D1 U6.4(V-) U6.6 U6.7 U7.14 U7.15 U7.16 U7.PAD U11.3 U12.4(V-) U15.2 U17.5 U18.1 U18.2 U20.4(V-) U22.4(V-)
V1A: R34.1 U17.15
V1B: R36.1 U17.2
V2A: R41.1 U17.7
V2B: R42.1 U17.10
VCC: C9.1 C18.1 C19.1 U3.3 U4.4 U4.5(VIN)
+VEXC: C45.2(N2) C54.1 D5.2 R14.2(N2) R24.1 U9.1 U11.2
-VEXC: C67.1 C68.2(N2) D5.1 R27.2(N2) U9.7 U11.8
AD8253_A0: U7.38 U7.40 U15.4 U18.4
AD8253_A1: U7.2 U15.5 U18.5
AD8253_WR0: U7.29 U15.6(WR_N)
AD8253_WR1: U7.46 U18.6(WR_N)
ADC0: C64.1 R52.2(N2) R53.2(N2) U7.8
ADC1: C72.1 R38.2(N2) R39.2(N2) U7.9
ADC2: C63.1 R31.2(N2) R32.2(N2) U7.10
ADC3: C52.1 R20.2(N2) R21.2(N2) U7.11
DAC: R16.1 U7.19
FB1: C21.1 D1.C E2.1 R3.1
FB2: C23.1 D2.A(P) E3.1 R57.1
LCD_A0: U1.15 U7.33
LCD_BACKLIGHT_LED+: R6.2(N2) U1.A U6.2
LCD_BACKLIGHT_LED-: U1.K U6.1
LCD_CSB: U1.17 U7.32
LCD_MOSI: U1.13 U7.31
LCD_RST: U1.16 U7.34
LCD_SCLK: U1.14 U7.30
PWM0: U7.41 U11.6
PWM1: U7.42 U17.8 U17.16
PWM2: U7.44 U17.1 U17.9
SWCLK: J4.4 R10.2(N2) U7.47
SWDIO: J4.2 R54.2(N2) U7.48
UNNAMED_2_AD8592_I160_: U6.8 U6.9
UNNAMED_2_AD8592_I160__1: C28.2(N2) R7.1 R8.2(N2) U6.3
UNNAMED_2_ADUCM36X_I1_AIN5: C41.1 J3.3 U7.22
UNNAMED_2_ADUCM36X_I1_AIN6: C37.1 J3.2 U7.23
UNNAMED_2_ADUCM36X_I1_AIN7: C39.1 R13.1 U7.24
UNNAMED_2_ADUCM36X_I1_AIN9: C36.1 J3.4(N4) R11.2(N2) R12.1 U7.26
UNNAMED_2_ADUCM36X_I1_AVDDREG: C44.1 C56.1 U7.7 U7.18
UNNAMED_2_ADUCM36X_I1_INTREF: C42.1 U7.20
UNNAMED_2_ADUCM36X_I1_P0: J2.2 U7.35
UNNAMED_2_ADUCM36X_I1_P0_1: J2.4 U7.36
UNNAMED_2_ADUCM36X_I1_P1: S1.A U7.39
UNNAMED_2_ADUCM36X_I1_P1_1: S1.B U7.43
UNNAMED_2_ADUCM36X_I1_P1_2: S1.1 U7.45
UNNAMED_2_ADUCM36X_I1_P2: R17.2(N2) R18.1 U7.3
UNNAMED_2_ADUCM36X_I1_RESETN: S2.2 U7.1
UNNAMED_2_CAP_I152_N1: C34.1 U1.6
UNNAMED_2_CAP_I152_N2: C34.2(N2) U1.7
UNNAMED_2_CAP_I153_N1: C33.1 U1.8
UNNAMED_2_CAP_I153_N2: C33.2(N2) U1.9
UNNAMED_2_CAP_I154_N1: C32.1 U1.10
UNNAMED_2_CAP_I156_N1: C1.1 U1.1
UNNAMED_2_CAP_I171_N1: C51.1 U1.2
UNNAMED_2_CAP_I172_N1: C101.1 U1.3
UNNAMED_2_CAP_I173_N1: C105.1 U1.4
UNNAMED_2_CAP_I174_N1: C106.1 U1.5
UNNAMED_2_CN4P_I8_N1: C38.1 J3.1 R13.2(N2) U7.25
UNNAMED_2_CN10PODDEVEN_I92_N5: J4.10(N5) S2.1
UNNAMED_2_CN10PODDEVEN_I95_N1: J4.1 R9.2(N2)
UNNAMED_2_DIO_I30_N: D4.C Q1.3 U2.P
UNNAMED_2_RES_I133_N2: Q1.1 R18.2(N2)
UNNAMED_3_ADA40772_I167_: C45.1 R14.1 R15.2(N2) U9.2
UNNAMED_3_ADA40772_I167__1: C49.1 R16.2(N2) U9.3
UNNAMED_3_ADA40772_I180_: C68.1 R24.2(N2) R27.1 U9.6
UNNAMED_3_ADA40772_I180__1: C59.1 R22.2(N2) U9.5
UNNAMED_3_ADP2301_I1_BST: C17.2(N2) U4.1
UNNAMED_3_ADP2301_I1_FB: R2.1 R5.2(N2) U4.3
UNNAMED_3_ADP2301_I1_SW: C17.1 D3.C L2.1 U4.6
UNNAMED_3_ADP5072_I216_AVIN: C12.1 C25.1 C26.1 C31.1 E1.1 L1.2(N2) L2.2(N2) R5.1 U5.A1 U5.B1 U5.B2 U5.C1 U5.C2 U5.C4 U5.D2
UNNAMED_3_ADP5072_I216_COMP1: R1.1 U5.E4
UNNAMED_3_ADP5072_I216_COMP2: R59.1 U5.E1
UNNAMED_3_ADP5072_I216_FB1: R3.2(N2) R4.1 U5.D4
UNNAMED_3_ADP5072_I216_FB2: R57.2(N2) R58.1 U5.E2
UNNAMED_3_ADP5072_I216_SW2: D2.C L3.2(N2) U5.A2
UNNAMED_3_ADP5072_I216_SW11: D1.A(P) L1.1 U5.A3 U5.B3
UNNAMED_3_ADP5072_I216_VREF: C13.1 R58.2(N2) U5.E3(VREF)
UNNAMED_3_CAP_I106_N1: C15.1 J1.1 U3.2(S)
UNNAMED_3_CAP_I220_N1: C24.1 R1.2(N2)
UNNAMED_3_CAP_I221_N1: C16.1 R59.2(N2)
UNNAMED_4_AD8253_I20_OUT: R45.1 U18.7
UNNAMED_4_AD8253_I20_REF: C92.1 U18.9 U22.1 U22.2
UNNAMED_4_AD8253_I171_INNEG: C103.2(N2) JP2.2(N2) JP4.2(N2) U15.1
UNNAMED_4_AD8253_I171_INPOS: C78.2(N2) R35.2(N2) U14.1 U15.10
UNNAMED_4_AD8253_I171_OUT: R33.1 U15.7
UNNAMED_4_AD8253_I171_REF: C79.1 U15.9 U22.6 U22.7
UNNAMED_4_ADA46X7_I119_: C95.1 J5.4 R47.1 U19.2
UNNAMED_4_ADA46X7_I119__1: C83.1 R40.2(N2) U19.3
UNNAMED_4_ADA46X7_I119_OUT: C95.2(N2) R47.2(N2) U18.10 U19.6
UNNAMED_4_ADA46221V2_I6_: C78.1 R35.1 U14.4
UNNAMED_4_ADG1419_I1_D: R23.2(N2) U11.1
UNNAMED_4_ADG1611_I193_S1: R33.2(N2) U17.3 U17.14
UNNAMED_4_ADG1611_I193_S3: R45.2(N2) U17.6 U17.11
UNNAMED_4_CAP_I166_N1: C103.1 J5.2 JP2.1
UNNAMED_4_CAP_I167_N1: C104.1 J5.3 JP3.1
UNNAMED_4_CAP_I167_N2: C104.2(N2) JP3.2(N2) JP5.1 U14.3
UNNAMED_4_CAP_I168_N1: C102.1 D5.3(N3) JP1.2(N2) R23.1
UNNAMED_4_CAP_I168_N2: C102.2(N2) J5.1 JP1.1
UNNAMED_4_NC2P_I230_N1: JP4.1 R55.1
UNNAMED_4_NC2P_I231_N2: JP5.2(N2) R56.2(N2)
UNNAMED_5_ADA45282_I8_: C75.1 R29.2(N2) R31.1 U12.2
UNNAMED_5_ADA45282_I8__1: C74.1 R28.2(N2) U12.3
UNNAMED_5_ADA45282_I8_OUT: C75.2(N2) R32.1 U12.1
UNNAMED_5_ADA45282_I25_: C62.1 R26.2(N2) U12.5
UNNAMED_5_ADA45282_I25__1: C55.1 R19.2(N2) R20.1 U12.6
UNNAMED_5_ADA45282_I25_OUT: C55.2(N2) R21.1 U12.7
UNNAMED_5_ADA45282_I43_: C89.1 R44.2(N2) U20.5
UNNAMED_5_ADA45282_I43__1: C85.1 R37.2(N2) R38.1 U20.6
UNNAMED_5_ADA45282_I43_OUT: C85.2(N2) R39.1 U20.7
UNNAMED_5_ADA45282_I56_: C96.1 R48.2(N2) R52.1 U20.2
UNNAMED_5_ADA45282_I56__1: C94.1 R46.2(N2) U20.3
UNNAMED_5_ADA45282_I56_OUT: C96.2(N2) R53.1 U20.1
UNNAMED_5_ADOPAMP1V4_I4_INV: C76.1 R30.1 U13.2
UNNAMED_5_ADOPAMP1V4_I4_NINV: C73.1 R36.2(N2) U13.3
UNNAMED_5_ADOPAMP1V4_I4_OUT: C76.2(N2) R29.1 R30.2(N2) U13.6
UNNAMED_5_ADOPAMP1V4_I21_INV: C60.1 R25.1 U10.2
UNNAMED_5_ADOPAMP1V4_I21_NINV: C50.1 R34.2(N2) U10.3
UNNAMED_5_ADOPAMP1V4_I21_OUT: C60.2(N2) R19.1 R25.2(N2) U10.6
UNNAMED_5_ADOPAMP1V4_I49_INV: C87.1 R43.1 U16.2
UNNAMED_5_ADOPAMP1V4_I49_NINV: C84.1 R41.2(N2) U16.3
UNNAMED_5_ADOPAMP1V4_I49_OUT: C87.2(N2) R37.1 R43.2(N2) U16.6
UNNAMED_5_ADOPAMP1V4_I61_INV: C97.1 R51.1 U21.2
UNNAMED_5_ADOPAMP1V4_I61_NINV: C93.1 R42.2(N2) U21.3
UNNAMED_5_ADOPAMP1V4_I61_OUT: C97.2(N2) R48.1 R51.2(N2) U21.6
VMID: C99.1 C100.1 R26.1 R28.1 R44.1 R46.1 R49.2(N2) R50.1 U22.3 U22.5
XTALI: C65.1 U7.5 Y1.2(N2)
XTALO: C66.1 U7.4(XTALO) Y1.1

Pads without a net: J2 3 6 8 9 10; J4 6 7 8 9; U5 C3 D3; U7 12 13 21 27 28; U10 1 5 8; U11 5; U13 1 5 8; U16 1 5 8; U17 12; U19 1 5 8; U21 1 5 8

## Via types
v1: diameter 0.508, hole 0.254, TOP to BOTTOM, 488 vias

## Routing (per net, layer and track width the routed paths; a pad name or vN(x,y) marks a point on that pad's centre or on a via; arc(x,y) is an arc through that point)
+3.3V: length 378.7
  TOP w0.8: v1(68.14,5.88) 66.14,3.88 42.39,3.88 41.04,5.22 v1(34.88,5.22) C8.1 v1(26.51,5.22) 10.44,5.22 6.48,9.18 v1(6.48,41.3) ; 95.87,45.97 v1(95.87,45.96) 95.87,41.5 99.41,37.96 99.41,21.71 100.54,20.58 v1(101.69,20.58) v1(105.98,20.58) v1(105.98,14.48) ; 95.87,45.97 90.94,45.97 ; 95.87,45.97 95.87,55.36 95.87,55.37 ; v1(81.88,48.88) 90.38,48.88 90.94,48.33 90.94,45.97 ; 95.87,55.37 J2.1 ; 95.87,55.37 95.87,65.1 93.78,67.18 v1(67.69,67.18) 62.29,67.18 60.06,64.96 U1.12 ; 70.49,37.68 v1(70.49,40.48) ; 70.49,37.68 v1(77.89,37.68) 79.98,37.68 80.59,38.28 80.59,42.88 81.48,43.78 89.59,43.78 90.94,45.13 90.94,45.97 ; 70.49,37.68 68.14,35.33 v1(68.14,32.33) v1(68.14,14.63)
  BOTTOM w0.203: U6.10 C27.1 ; C40.1 81.72,47.38 81.09,46.75 U7.37 ; U7.17 71.96,43.25 C48.1 ; 65.91,32.41 U12.8 ; C57.1 76.91,38.25 77.01,38.35 U7.6 ; v1(26.51,5.22) 26.51,6 26.36,6.15 U22.8 ; R11.1 v1(6.48,41.3) ; U6.5 R6.1 ; U20.8 C91.1
  BOTTOM w0.5: R54.1 v1(105.98,20.58) ; R9.1 v1(101.69,20.58) ; 65.91,32.41 C71.1 68.06,32.41 v1(68.14,32.33) ; v1(77.89,37.68) 77.69,37.48 C57.1 ; C91.1 v1(68.14,14.63) v1(68.14,5.88) ; R17.1 95.82,42.32 Q1.2 95.87,42.37 C43.1 v1(95.87,45.96) ; R10.1 v1(105.98,14.48) ; R49.1 35.43,6.72 34.88,6.18 v1(34.88,5.22) ; C48.1 v1(70.49,40.48) ; U1.12 C35.1 ; C40.1 v1(81.88,48.88)
  BOTTOM w1: 68.43,73.45 73.62,73.45 75.88,71.18 C27.1 ; 68.43,73.45 C28.1 ; 68.43,73.45 68.4,73.48 40.09,73.48 39.38,74.18 C81.1 E1.2
+15V: length 202
  TOP w0.5: v1(31.21,16.6) 31.29,16.68 C4.1
  TOP w0.8: v1(24.68,14.98) 26.08,13.58 26.98,13.58 ; v1(56.28,7.88) v1(56.28,17.28) 56.18,17.38 v1(56.18,28.98) v1(56.18,39.48) 56.18,44.58 54.29,46.48 46.09,46.48 45.19,45.58 45.19,29.78 40.98,25.58 30.58,25.58 ; v1(15.36,62.56) 15.36,37.8 16.06,37.1 v1(16.06,35.06) 16.06,32 17.09,30.98 v1(30.38,30.98) 30.58,30.78 30.58,25.58 ; 30.58,25.58 29.29,25.58 28.18,24.48 v1(28.18,23.48) ; v1(28.18,23.48) 28.17,23.47 28.17,17.1 28.67,16.6 v1(31.21,16.6) ; v1(28.18,23.48) v1(25.48,23.48) C3.1 ; v1(28.17,13.56) 28.15,13.58 26.98,13.58 ; 26.98,13.58 v1(26.98,10.08)
  BOTTOM w0.203: U14.5 23.26,23.17 23.58,23.48 v1(25.48,23.48) ; C7.1 26.06,10.1 U19.7 ; v1(28.18,23.48) 28.17,23.47 U15.8 ; C58.1 30.67,33.26 U9.8 ; U11.4 C53.1 ; U17.13 v1(31.21,16.6) ; U18.8 v1(28.17,13.56)
  BOTTOM w0.5: U16.7 54.77,18.7 C88.1 55.78,18.48 56.28,17.98 v1(56.28,17.28) ; C86.1 v1(24.68,14.98) ; U13.7 54.85,29.19 C77.1 v1(56.18,28.98) ; C7.1 v1(26.98,10.08) ; U21.7 54.66,8.21 C98.1 v1(56.28,7.88) ; v1(56.18,39.48) C61.1 54.86,39.68 U10.7 ; C53.1 v1(16.06,35.06) ; C58.1 v1(30.38,30.98)
  BOTTOM w0.8: v1(28.17,13.56) 28.17,13.79 30.98,16.6 v1(31.21,16.6) ; E2.2 v1(15.36,62.56)
  BOTTOM w1: E2.2 C29.1
-15V: length 190.6
  TOP w0.5: v1(37.08,38.18) 32.38,33.48 v1(26.38,33.48)
  TOP w0.8: 16.88,17.08 v1(25.29,17.08) 27,15.36 v1(28.17,15.36) 31.57,15.36 35.89,19.68 40.39,19.68 41.19,18.88 C6.1 ; 16.88,17.08 16.88,13.42 17.66,12.64 C5.1 v1(20.32,12.64) ; 16.88,17.08 16.88,25.99 v1(16.84,26.02) ; v1(16.84,26.02) 15.34,26.02 13.29,28.08 v1(13.29,62.58) ; v1(16.84,26.02) C2.1 24.23,26.02 26.29,28.08 v1(27.88,28.08) ; v1(47.43,45.23) v1(47.43,35.03) v1(47.43,24.13) 47.39,24.09 47.39,16.58 ; 47.39,16.58 v1(47.39,13.78) ; 47.39,16.58 47.36,16.6 C6.1 ; C6.1 v1(40.06,16.6)
  BOTTOM w0.203: v1(25.29,17.08) 25.17,17.2 C82.1 ; U9.4 35.46,37.86 C46.1 ; C70.1 25.11,33.75 U11.7 ; U15.3 28.17,27.8 v1(27.88,28.08) ; U19.4 v1(20.32,12.64) ; U14.2 20.37,24.12 20.92,24.67 20.92,25.45 20.34,26.02 v1(16.84,26.02) ; U17.4 v1(40.06,16.6) ; U18.3 v1(28.17,15.36)
  BOTTOM w0.5: U13.4 C69.1 v1(47.43,35.03) ; U21.4 47.43,12.53 C90.1 v1(47.39,13.78) ; v1(27.88,28.08) 27.88,31.98 v1(26.38,33.48) C70.1 ; C46.1 v1(37.08,38.18) ; v1(47.43,24.13) C80.1 U16.4 ; U10.4 C47.1 v1(47.43,45.23)
  BOTTOM w0.8: E3.2 v1(13.29,62.58)
  BOTTOM w1: E3.2 C30.1
GND: length 392.2
  TOP w0.4: 90.97,10.68 S1.SH1 ; S1.SH1 92.56,12.52 ; S1.SH1 94.15,10.68 ; S1.SH1 92.56,8.84 ; 41.19,14.28 C6.2 ; C6.2 40.44,15 ; C6.2 41.93,15 ; 108.16,43.05 U2.N ; U2.N 107.21,44 ; U2.N 109.11,44 ; U2.N 108.16,44.95 ; 26.74,3.62 C8.2 ; C8.2 27.48,4.34 ; C8.2 28.23,3.62 ; C8.2 27.48,2.9 ; 83.96,3.68 84.98,3.68 ; 83.96,3.68 83.96,4.7 ; 83.96,3.68 82.94,3.68 ; 83.96,3.68 83.96,2.67 ; C3.2 24.08,22.61 ; C3.2 23.34,21.88 ; C3.2 24.83,21.88 ; C3.2 24.08,21.16 ; 18.8,13.52 C5.2 ; C5.2 19.55,14.24 ; C5.2 18.8,14.97 ; C5.2 18.05,14.24 ; 58.56,55.61 U1.11 58.56,57.39 ; S2.3 102.52,32.96 ; S2.3 101.56,31.66 ; S2.3 100.61,32.96 ; S2.3 101.56,34.27 ; J5.5 3.7,12.19 ; J5.5 4.84,11.05 ; J5.5 3.7,9.91 ; J5.5 2.55,11.05 ; J2.5 102.54,61.53 ; J2.5 102.54,59.37 ; J2.5 101.46,60.45 ; J2.5 103.62,60.45 ; 80.36,10.68 81.95,10.68 ; 80.36,10.68 78.77,10.68 ; 80.36,10.68 80.36,8.84 ; 80.36,10.68 80.36,12.52 ; C4.2 32.03,19.18 ; C4.2 31.29,18.46 ; C4.2 31.29,19.9 ; 101.46,62.99 J2.7 ; J2.7 102.54,61.91 ; J2.7 103.62,62.99 ; J2.7 102.54,64.07 ; 17.24,27.62 C2.2 ; C2.2 17.98,26.9 ; C2.2 17.98,28.35 ; C2.2 18.73,27.62 ; S1.C 86.46,19.2 ; S1.C 87.48,18.18 ; S1.C 86.46,17.17 ; S1.C 85.44,18.18 ; J1.3 9.54,93.54 ; J1.3 11,92.08 ; J1.3 8.08,92.08 ; J1.3 9.54,90.61 ; S2.4 102.52,23.86 ; S2.4 100.61,23.86 ; S2.4 101.56,22.55 ; S2.4 101.56,25.16 ; 12.78,95.08 J1.2 ; J1.2 14.24,93.61 ; J1.2 15.7,95.08 ; J1.2 14.24,96.54
  TOP w0.5: 101.89,16.88 v1(101.92,16.91) J4.3 ; J4.5 v1(102.02,15.64) 101.98,15.68
  BOTTOM w0.203: U6.7 73.02,65.5 ; 68.68,65.29 68.9,65.5 U6.4 70.66,65.5 ; 13.23,77.22 U5.D1 ; U5.B4 U5.A4 15.36,75.51 15.41,75.51 v1(15.81,75.11) ; U7.16 U7.15 ; 27.58,25.28 27.67,25.36 U15.2 27.67,27.1 27.48,27.28 ; U11.3 18.01,34.41 v1(17.68,34.08) ; U18.1 U18.2 27.67,17.6 27.64,17.62 27.64,17.78
  BOTTOM w0.4: 54.3,27.38 C77.2 ; C77.2 55.05,28.1 ; C77.2 55.05,26.66 ; C77.2 55.8,27.38 ; 12.88,11.37 R40.1 ; R40.1 13.44,12.07 ; R40.1 13.44,10.67 ; R40.1 13.99,11.37 ; S1.C 87.48,18.18 ; S1.C 86.46,19.2 ; S1.C 85.44,18.18 ; S1.C 86.46,17.17 ; C51.2 45.81,52.48 ; C51.2 45.06,51.76 ; C51.2 45.06,53.2 ; C51.2 44.31,52.48 ; R56.1 9.72,23.78 ; R56.1 9.16,23.08 ; R56.1 9.16,24.48 ; R56.1 8.6,23.78 ; 54.3,37.88 C61.2 ; C61.2 55.8,37.88 ; C61.2 55.05,37.16 ; C61.2 55.05,38.6 ; 72.39,67.78 R7.2 ; R7.2 73.68,67.78 ; R7.2 73.03,68.53 ; R7.2 73.03,67.03 ; 108.16,43.05 U2.N ; U2.N 107.21,44 ; U2.N 109.11,44 ; U2.N 108.16,44.95 ; 35.79,35.86 C46.2 ; C46.2 35.79,37.3 ; C46.2 36.53,36.58 ; C46.2 35.04,36.58 ; C38.2 10.59,58.79 ; C38.2 11.31,58.04 ; C38.2 10.59,57.29 ; C38.2 9.86,58.04 ; C7.2 26.83,8.48 ; C7.2 26.08,7.76 ; C7.2 25.34,8.48 ; C7.2 26.08,9.2 ; J5.5 4.84,11.05 ; J5.5 2.55,11.05 ; J5.5 3.7,12.19 ; J5.5 3.7,9.91 ; 18.59,64.23 C29.2 ; C29.2 18.59,65.73 ; C29.2 19.31,64.98 ; U22.4 31.49,2.34 ; U22.4 29.16,2.34 ; U22.4 30.32,1.77 ; C101.2 46.56,53.2 ; C101.2 47.31,52.48 ; C101.2 46.56,51.76 ; C101.2 45.81,52.48 ; 80.09,35.83 C65.2 ; C65.2 79.36,36.58 ; C65.2 80.09,37.33 ; C65.2 80.81,36.58 ; 44.89,31.33 C73.2 ; C73.2 44.14,32.06 ; C73.2 44.89,32.78 ; C73.2 45.64,32.06 ; 82.76,47.38 C40.2 ; C40.2 83.49,46.63 ; C40.2 83.49,48.13 ; C40.2 84.21,47.38 ; C53.2 17.83,36.66 ; C53.2 16.34,36.66 ; C53.2 17.09,37.38 ; C53.2 17.09,35.93 ; 10.59,55.73 C39.2 ; C39.2 11.31,56.48 ; C39.2 10.59,57.23 ; C39.2 9.86,56.48 ; R15.1 30.79,43.18 ; R15.1 30.23,42.48 ; R15.1 31.34,42.48 ; 68.16,43.78 C56.2 ; C56.2 69.61,43.78 ; C56.2 C42.2 ; 20.54,90.38 C9.2 ; C9.2 22.03,90.38 ; C9.2 21.29,89.66 ; 48.81,52.48 C106.2 ; C106.2 49.56,51.76 ; C106.2 49.56,53.2 ; C106.2 50.31,52.48 ; C90.2 45.78,13.33 ; C90.2 45.78,11.83 ; C90.2 46.51,12.58 ; C90.2 45.06,12.58 ; 68.16,45.28 C42.2 ; C42.2 69.61,45.28 ; 19.89,77.23 R4.2 ; R4.2 20.53,77.98 ; R4.2 21.18,77.23 ; R4.2 20.53,76.48 ; 32.88,87.9 D3.A ; D3.A 35.09,87.9 ; D3.A 33.98,86.4 ; D3.A 33.98,89.4 ; 40.99,76.13 C81.2 ; C81.2 40.99,77.63 ; C81.2 41.71,76.88 ; C50.2 44.89,43.27 ; C50.2 44.14,42.55 ; C50.2 44.89,41.82 ; C50.2 45.64,42.55 ; 28.76,90.13 U4.2 28.76,88.4 ; C94.2 60.61,10.68 ; C94.2 59.16,10.68 ; C94.2 59.88,9.93 ; 56.31,52.48 C32.2 ; C32.2 57.81,52.48 ; C32.2 57.06,51.76 ; C32.2 57.06,53.2 ; D4.A 104.55,41.38 ; D4.A 103.13,41.38 ; D4.A 103.84,42.24 ; D4.A 103.84,40.52 ; C16.2 12.49,84.8 ; C16.2 13.23,84.08 ; C16.2 12.49,83.36 ; C16.2 11.74,84.08 ; C44.2 76.13,35.88 ; C44.2 75.39,35.16 ; C44.2 75.39,36.6 ; C44.2 74.64,35.88 ; C54.2 18.58,37.53 ; C54.2 18.58,36.03 ; C54.2 19.31,36.78 ; C54.2 17.86,36.78 ; 47.31,52.48 C105.2 ; C105.2 48.06,51.76 ; C105.2 48.81,52.48 ; C105.2 48.06,53.2 ; U12.4 63.36,28.72 ; U12.4 62.95,27.81 ; U12.4 63.36,26.89 ; C89.2 59.88,15.38 ; C89.2 59.16,14.63 ; C89.2 60.61,14.63 ; 69.61,41.78 C48.2 68.88,41.03 ; 58.56,57.39 U1.11 58.56,55.61 ; C62.2 59.94,33.16 ; C62.2 60.66,32.41 ; C62.2 59.21,32.41 ; C58.2 30.38,35.3 ; C58.2 31.13,34.58 ; C58.2 30.38,33.86 ; C80.2 46.56,23.18 ; C80.2 45.83,22.43 ; C80.2 45.83,23.93 ; C80.2 45.11,23.18 ; C66.2 82.31,36.58 ; C66.2 81.58,35.83 ; C66.2 81.58,37.33 ; C66.2 80.86,36.58 ; 102.54,61.91 J2.7 ; J2.7 101.46,62.99 ; J2.7 102.54,64.07 ; J2.7 103.62,62.99 ; 80.36,10.68 80.36,12.52 ; 80.36,10.68 80.36,8.84 ; 80.36,10.68 81.95,10.68 ; 80.36,10.68 78.77,10.68 ; 16.44,69.89 C21.2 ; C21.2 17.18,70.61 ; C21.2 17.93,69.89 ; 33.79,1.6 C99.2 ; C99.2 34.53,2.32 ; C99.2 33.04,2.32 ; C99.2 33.79,3.04 ; 45.11,33.78 C69.2 ; C69.2 45.83,34.53 ; C69.2 46.56,33.78 ; C69.2 45.83,33.03 ; 59.94,27.63 C74.2 ; C74.2 59.21,28.38 ; C74.2 60.66,28.38 ; C1.2 43.56,53.2 ; C1.2 43.56,51.76 ; C1.2 42.81,52.48 ; C1.2 44.31,52.48 ; C83.2 16.93,12.97 ; C83.2 15.44,12.97 ; C83.2 16.18,13.7 ; C83.2 16.18,12.25 ; C100.2 36.13,2.32 ; C100.2 35.38,1.6 ; C100.2 35.38,3.04 ; C100.2 34.64,2.32 ; C19.2 26.08,91.01 ; C19.2 26.08,89.56 ; C19.2 26.83,90.28 ; C19.2 25.34,90.28 ; 24.29,89.56 C18.2 ; C18.2 25.03,90.28 ; C18.2 24.29,91.01 ; C18.2 23.54,90.28 ; J2.5 102.54,61.53 ; J2.5 102.54,59.37 ; J2.5 103.62,60.45 ; J2.5 101.46,60.45 ; C92.2 29.16,8.48 ; C92.2 28.43,7.73 ; C92.2 27.71,8.48 ; C27.2 77.49,64.75 ; C27.2 78.21,64 ; C27.2 77.49,63.25 ; 76.16,35.88 C57.2 ; C57.2 76.91,36.6 ; C57.2 77.66,35.88 ; C57.2 76.91,35.16 ; 73.89,35.16 C64.2 ; C64.2 73.89,36.6 ; C64.2 74.63,35.88 ; C37.2 7.38,52.08 ; C37.2 8.13,51.36 ; C37.2 6.64,51.36 ; C37.2 7.38,50.63 ; 10.08,64.23 C30.2 ; C30.2 9.36,64.98 ; C30.2 10.08,65.73 ; 92.56,8.84 S1.SH1 ; S1.SH1 94.15,10.68 ; S1.SH1 92.56,12.52 ; S1.SH1 90.97,10.68 ; 67.08,30.08 C71.2 ; C71.2 66.34,30.81 ; C71.2 67.83,30.81 ; C71.2 67.08,31.53 ; U6.6 73.98,66.41 ; U6.6 74.9,66 ; U6.6 73.07,66 ; 25.38,31.16 C70.2 ; C70.2 26.13,31.88 ; C70.2 24.64,31.88 ; C70.2 25.38,32.6 ; C86.2 24.32,16.58 ; C86.2 23.57,17.3 ; C86.2 22.82,16.58 ; C86.2 23.57,15.85 ; C43.2 98.19,44.28 ; C43.2 96.74,44.28 ; C43.2 97.47,45.03 ; C43.2 97.47,43.53 ; J1.2 14.24,96.54 ; J1.2 15.7,95.08 ; J1.2 12.78,95.08 ; 83.96,3.68 84.98,3.68 ; 83.96,3.68 82.94,3.68 ; 83.96,3.68 83.96,4.7 ; 83.96,3.68 83.96,2.67 ; 36.66,33.26 C59.2 ; C59.2 37.39,32.51 ; C59.2 38.11,33.26 ; C35.2 60.06,53.2 ; C35.2 60.06,51.76 ; C35.2 60.81,52.48 ; C35.2 59.31,52.48 ; 67.44,35.88 C52.2 ; C52.2 68.19,35.16 ; C52.2 68.19,36.6 ; C47.2 49.03,44.83 ; C47.2 49.76,44.08 ; C47.2 49.03,43.33 ; C47.2 48.31,44.08 ; C67.2 24.51,36.78 ; C67.2 23.06,36.78 ; C67.2 23.79,36.03 ; C67.2 23.79,37.53 ; R55.2 9.16,29.53 ; R55.2 9.16,28.13 ; R55.2 8.6,28.83 ; R55.2 9.72,28.83 ; R12.2 8.79,41.75 ; R12.2 9.53,41.1 ; R12.2 8.79,40.45 ; 54.24,6.28 C98.2 ; C98.2 54.98,5.56 ; C98.2 54.98,7 ; C98.2 55.73,6.28 ; 16.83,90.46 U3.1 ; U3.1 16.83,91.58 ; U3.1 17.61,91.02 ; C25.2 41.71,84.98 ; C25.2 40.99,84.23 ; C25.2 40.99,85.73 ; 23.57,17.53 C82.2 ; C82.2 22.84,18.28 ; C82.2 23.57,19.03 ; C82.2 24.29,18.28 ; C26.2 41.71,83.28 ; C26.2 40.99,82.53 ; C26.2 40.99,84.03 ; C79.2 24.29,19.93 ; C79.2 22.84,19.93 ; C79.2 23.57,19.18 ; C79.2 23.57,20.68 ; 33.86,40.66 C49.2 33.86,42.1 ; 36.19,2.42 R50.2 ; R50.2 36.89,2.98 ; R50.2 37.58,2.42 ; R50.2 36.89,1.86 ; 62.95,10.03 U20.4 ; U20.4 63.36,10.95 ; U20.4 63.36,9.12 ; 54.24,16.88 C88.2 ; C88.2 54.98,17.6 ; C88.2 54.98,16.16 ; 10.38,40.47 C36.2 ; C36.2 10.38,41.92 ; C36.2 11.13,41.2 ; C36.2 9.64,41.2 ; 44.14,21.57 C84.2 ; C84.2 44.89,20.84 ; C84.2 45.64,21.57 ; C84.2 44.89,22.29 ; 66.24,13.03 C91.2 ; C91.2 66.98,12.31 ; C91.2 66.98,13.76 ; 37.48,84.58 R2.2 38.04,85.28 ; 6.64,46.28 C41.2 ; C41.2 7.38,45.55 ; C41.2 8.13,46.28 ; C41.2 7.38,47 ; C15.2 12.64,92.73 ; C15.2 12.64,91.23 ; C15.2 11.92,91.98 ; C31.2 41.71,81.68 ; C31.2 40.99,82.43 ; C31.2 40.99,80.93 ; J1.3 11,92.08 ; J1.3 9.54,90.61 ; J1.3 8.08,92.08 ; J1.3 9.54,93.54 ; R22.1 37.84,34.68 ; R22.1 37.28,35.38 ; R22.1 36.73,34.68 ; C24.2 16.09,84.8 ; C24.2 15.34,84.08 ; C24.2 16.83,84.08 ; C24.2 16.09,83.36 ; 11.19,72.78 L3.1 ; L3.1 11.96,74.14 ; L3.1 11.96,71.42 ; C12.2 11.93,76.68 ; C12.2 10.44,76.68 ; C12.2 11.19,75.96 ; C23.2 11.48,70.61 ; C23.2 12.23,69.89 ; C23.2 10.74,69.89 ; 13.84,82.98 C13.2 ; C13.2 14.59,82.26 ; C13.2 14.59,83.7 ; 27.17,15.66 U18.1 ; U18.1 27.17,17.49 ; U18.1 26.76,16.58 ; 44.14,11.08 C93.2 ; C93.2 44.89,11.8 ; C93.2 44.89,10.35 ; C93.2 45.64,11.08 ; 37.53,15.95 U17.5 39.69,15.95
  BOTTOM w0.5: C63.2 v1(70.09,34.68) ; C72.2 v1(71.98,34.78)
  vias: v1(7.29,50.18) v1(7.29,45.18) v1(8.29,38.68) v1(8.29,28.88) v1(8.29,23.78) v1(8.59,2.88) v1(8.69,40.08) v1(9.09,64.88) v1(9.29,35.98) v1(9.38,18.28) v1(9.59,34.38) v1(10.19,40.18) v1(10.38,45.88) v1(10.79,14.38) v1(10.98,84.08) v1(11.09,38.98) v1(11.48,70.98) v1(11.48,27.68) v1(11.59,91.98) v1(11.59,57.98) v1(11.69,56.38) v1(11.69,30.18) v1(12.19,77.78) v1(12.19,76.68) v1(12.19,16.28) v1(12.49,85.18) v1(12.59,11.28) v1(12.99,77.28) v1(13.19,25.88) v1(13.79,18.38) v1(13.99,8.68) v1(14.29,50.48) v1(14.29,44.68) v1(14.38,55.88) v1(14.49,84.08) v1(15.09,12.88) v1(15.19,22.38) v1(15.29,30.38) v1(15.88,14.08) v1(15.99,85.28) v1(16.29,7.58) v1(16.79,37.88) v1(16.79,27.58) v1(16.88,3.18) v1(17.09,70.98) v1(17.29,83.98) v1(17.59,37.88) v1(17.98,91.08) v1(18.29,56.28) v1(18.29,44.68) v1(18.38,15.38) v1(18.59,37.88) v1(18.79,81.68) v1(18.79,35.78) v1(18.98,19.78) v1(19.09,50.58) v1(19.09,41.68) v1(19.18,29.68) v1(19.18,27.58) v1(19.29,15.38) v1(19.68,64.88) v1(20.38,78.38) v1(21.08,32.58) v1(21.38,89.18) v1(21.38,35.28) v1(21.48,13.78) v1(21.58,77.38) v1(22.48,18.18) v1(22.58,15.88) v1(22.68,29.38) v1(22.68,20.48) v1(22.79,45.68) v1(24.08,80.08) v1(24.18,7.98) v1(24.29,89.08) v1(24.29,32.08) v1(24.29,20.88) v1(24.48,38.98) v1(24.68,36.18) v1(24.79,84.78) v1(24.79,37.18) v1(25.08,28.28) v1(25.29,41.98) v1(25.29,21.88) v1(25.38,15.68) v1(25.58,67.98) v1(25.79,62.98) v1(26.08,7.28) v1(26.29,89.08) v1(26.38,50.18) v1(26.58,31.98) v1(26.79,38.68) v1(26.98,36.88) v1(27.08,18.98) v1(27.08,17.78) v1(27.08,6.68) v1(27.08,2.28) v1(27.18,56.18) v1(27.18,14.48) v1(27.29,25.08) v1(27.29,8.48) v1(28.08,2.38) v1(28.18,72.48) v1(28.41,7.53) v1(28.79,90.48) v1(28.79,87.98) v1(29.88,67.68) v1(30.18,35.78) v1(30.38,43.48) v1(30.88,38.28) v1(30.98,22.48) v1(31.08,24.38) v1(31.18,36.08) v1(31.18,9.48) v1(31.29,43.48) v1(31.29,31.98) v1(31.29,12.78) v1(32.09,87.98) v1(32.09,50.28) v1(32.48,8.48) v1(32.69,26.58) v1(32.88,47.28) v1(33.29,42.38) v1(33.79,1.28) v1(33.88,86.08) v1(34.09,13.48) v1(34.19,42.38) v1(34.19,10.68) v1(34.59,65.88) v1(34.69,32.38) v1(34.69,24.48) v1(34.88,34.38) v1(35.48,1.28) v1(35.59,51.68) v1(35.79,29.78) v1(36.09,87.88) v1(36.29,14.48) v1(36.79,36.58) v1(36.79,1.28) v1(37.19,16.08) v1(37.39,26.58) v1(37.79,28.38) v1(37.89,32.08) v1(37.98,85.68) v1(37.98,13.18) v1(38.19,29.98) v1(38.29,1.68) v1(38.69,34.98) v1(38.79,34.08) v1(38.89,21.38) v1(38.98,23.88) v1(39.09,7.78) v1(39.48,38.78) v1(39.69,10.98) v1(40.09,15.58) v1(40.09,3.68) v1(40.39,69.98) v1(40.59,13.88) v1(41.09,78.28) v1(41.19,80.58) v1(41.69,13.88) v1(42.19,84.98) v1(42.19,83.18) v1(42.19,76.88) v1(42.29,37.78) v1(42.39,81.78) v1(42.48,14.88) v1(42.59,28.98) v1(42.89,35.28) v1(43.48,51.28) v1(43.59,6.98) v1(43.69,32.58) v1(43.69,31.68) v1(43.79,42.98) v1(43.79,42.18) v1(43.89,21.88) v1(43.89,21.18) v1(43.98,14.18) v1(44.59,25.58) v1(44.69,23.48) v1(44.69,22.78) v1(44.69,12.48) v1(45.09,51.28) v1(45.79,13.68) v1(45.89,11.18) v1(45.98,83.48) v1(46.19,36.88) v1(46.39,34.98) v1(46.39,32.68) v1(46.69,51.18) v1(47.69,90.68) v1(47.79,51.38) v1(49.19,33.88) v1(49.59,30.68) v1(49.69,51.28) v1(49.69,9.78) v1(49.79,20.48) v1(49.89,40.68) v1(50.09,44.58) v1(50.09,43.68) v1(50.19,12.18) v1(50.48,32.48) v1(50.59,22.98) v1(51.98,37.18) v1(52.19,15.18) v1(53.09,26.28) v1(53.29,13.18) v1(53.48,23.58) v1(53.59,35.78) v1(53.89,79.78) v1(54.09,43.38) v1(54.19,86.78) v1(54.19,33.18) v1(54.39,36.78) v1(54.39,4.98) v1(54.48,15.88) v1(54.69,21.38) v1(54.89,26.38) v1(55.09,61.08) v1(55.19,36.78) v1(55.29,15.88) v1(55.69,4.98) v1(56.59,93.58) v1(56.59,67.08) v1(57.19,51.28) v1(57.39,23.58) v1(57.69,16.98) v1(57.79,11.58) v1(57.98,32.18) v1(58.19,34.28) v1(58.39,77.98) v1(58.48,43.88) v1(59.09,81.88) v1(59.19,87.18) v1(59.59,41.38) v1(59.98,33.48) v1(60.09,27.28) v1(60.09,15.68) v1(60.19,24.08) v1(60.29,9.58) v1(60.39,51.18) v1(60.39,17.08) v1(60.69,37.38) v1(60.69,21.28) v1(62.69,27.78) v1(62.98,29.08) v1(63.09,61.78) v1(63.19,26.58) v1(63.19,11.28) v1(63.29,45.08) v1(63.29,24.38) v1(63.29,8.78) v1(64.08,41.68) v1(64.28,65.58) v1(64.28,12.98) v1(64.39,46.88) v1(64.78,94.68) v1(64.78,30.18) v1(65.89,12.98) v1(66.08,30.98) v1(66.48,19.38) v1(66.69,29.78) v1(66.69,27.68) v1(66.69,16.58) v1(66.78,45.28) v1(66.89,21.68) v1(66.98,12.08) v1(67.08,35.88) v1(67.28,85.18) v1(67.39,49.88) v1(67.78,45.28) v1(68.09,40.68) v1(68.89,61.88) v1(68.89,40.68) v1(68.98,56.48) v1(69.78,14.28) v1(69.89,32.18) v1(69.98,29.28) v1(69.98,22.08) v1(69.98,17.58) v1(70.09,24.28) v1(70.78,66.28) v1(70.78,65.68) v1(71.19,55.18) v1(71.28,15.08) v1(71.89,41.48) v1(71.89,40.58) v1(71.89,28.48) v1(71.98,32.08) v1(71.98,21.18) v1(72.78,66.08) v1(72.78,65.48) v1(72.78,40.58) v1(73.19,69.18) v1(73.89,34.78) v1(74.09,91.08) v1(74.81,45.81) v1(74.81,43.81) v1(74.81,41.81) v1(75.39,34.78) v1(75.59,26.68) v1(75.98,31.38) v1(75.98,9.28) v1(76.81,45.81) v1(76.81,43.81) v1(76.81,41.81) v1(76.89,34.88) v1(78.59,21.78) v1(78.69,30.08) v1(78.81,45.81) v1(78.81,43.81) v1(78.81,41.81) v1(78.89,64.08) v1(79.69,60.98) v1(79.71,14.71) v1(79.78,55.88) v1(79.89,31.88) v1(80.19,85.28) v1(80.39,47.78) v1(80.78,69.48) v1(80.89,35.58) v1(81.09,37.48) v1(82.78,59.18) v1(84.09,27.48) v1(84.28,33.38) v1(84.28,13.88) v1(84.59,47.48) v1(85.48,82.58) v1(85.78,61.18) v1(86.19,44.78) v1(86.48,20.88) v1(86.48,14.88) v1(87.09,47.78) v1(87.78,44.68) v1(87.78,32.28) v1(87.78,28.98) v1(88.09,45.88) v1(88.19,47.18) v1(88.39,73.18) v1(88.98,44.78) v1(89.48,47.58) v1(89.61,42.51) v1(89.69,32.08) v1(89.78,56.28) v1(89.89,46.18) v1(89.98,20.68) v1(90.19,29.28) v1(90.48,62.38) v1(90.71,41.81) v1(90.98,34.48) v1(92.28,24.08) v1(93.19,48.58) v1(93.28,14.98) v1(93.78,20.18) v1(94.09,44.88) v1(94.78,37.68) v1(95.19,33.08) v1(97.59,82.88) v1(97.91,27.41) v1(97.89,8.68) v1(98.09,53.98) v1(98.09,50.38) v1(98.48,68.88) v1(98.48,44.28) v1(98.59,47.48) v1(98.89,59.18) v1(99.59,17.28) v1(100.48,38.58) v1(101.61,31.31) v1(101.61,25.71) v1(101.69,77.18) v1(103.19,21.68) v1(103.81,28.21) v1(104.01,19.31) v1(104.39,37.98) v1(104.98,41.38) v1(105.28,48.68) v1(105.39,8.78) v1(107.41,15.51) v1(107.48,25.58) v1(109.51,34.31) v1(109.71,24.11) v1(109.69,11.58)
